VERSION 5.8 ;
BUSBITCHARS "[]" ;
DIVIDERCHAR "/" ;
UNITS
    DATABASE MICRONS 1000 ;
END UNITS

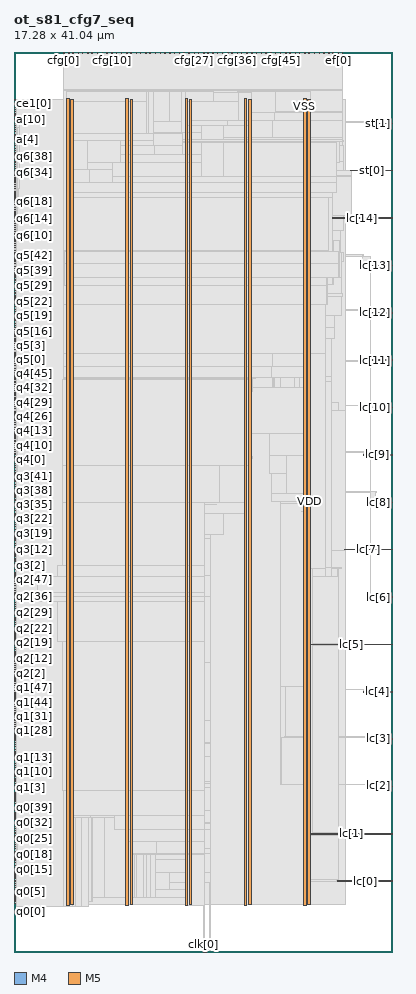
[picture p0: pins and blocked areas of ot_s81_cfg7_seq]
MACRO ot_s81_cfg7_seq
  FOREIGN ot_s81_cfg7_seq 0 0 ;
  CLASS BLOCK ;
  SIZE 17.28 BY 41.04 ;
  PIN a[0]
    DIRECTION OUTPUT ;
    USE SIGNAL ;
    PORT
      LAYER M4 ;
        RECT  0 36.96 0.084 36.984 ;
    END
  END a[0]
  PIN a[10]
    DIRECTION OUTPUT ;
    USE SIGNAL ;
    PORT
      LAYER M4 ;
        RECT  0 37.968 0.084 37.992 ;
    END
  END a[10]
  PIN a[11]
    DIRECTION OUTPUT ;
    USE SIGNAL ;
    PORT
      LAYER M4 ;
        RECT  0 38.112 0.084 38.136 ;
    END
  END a[11]
  PIN a[1]
    DIRECTION OUTPUT ;
    USE SIGNAL ;
    PORT
      LAYER M4 ;
        RECT  0 37.056 0.084 37.08 ;
    END
  END a[1]
  PIN a[2]
    DIRECTION OUTPUT ;
    USE SIGNAL ;
    PORT
      LAYER M4 ;
        RECT  0 37.152 0.084 37.176 ;
    END
  END a[2]
  PIN a[3]
    DIRECTION OUTPUT ;
    USE SIGNAL ;
    PORT
      LAYER M4 ;
        RECT  0 37.248 0.084 37.272 ;
    END
  END a[3]
  PIN a[4]
    DIRECTION OUTPUT ;
    USE SIGNAL ;
    PORT
      LAYER M4 ;
        RECT  0 37.392 0.084 37.416 ;
    END
  END a[4]
  PIN a[5]
    DIRECTION OUTPUT ;
    USE SIGNAL ;
    PORT
      LAYER M4 ;
        RECT  0 37.488 0.084 37.512 ;
    END
  END a[5]
  PIN a[6]
    DIRECTION OUTPUT ;
    USE SIGNAL ;
    PORT
      LAYER M4 ;
        RECT  0 37.584 0.084 37.608 ;
    END
  END a[6]
  PIN a[7]
    DIRECTION OUTPUT ;
    USE SIGNAL ;
    PORT
      LAYER M4 ;
        RECT  0 37.68 0.084 37.704 ;
    END
  END a[7]
  PIN a[8]
    DIRECTION OUTPUT ;
    USE SIGNAL ;
    PORT
      LAYER M4 ;
        RECT  0 37.776 0.084 37.8 ;
    END
  END a[8]
  PIN a[9]
    DIRECTION OUTPUT ;
    USE SIGNAL ;
    PORT
      LAYER M4 ;
        RECT  0 37.872 0.084 37.896 ;
    END
  END a[9]
  PIN ce0[0]
    DIRECTION OUTPUT ;
    USE SIGNAL ;
    PORT
      LAYER M4 ;
        RECT  0 38.208 0.084 38.232 ;
    END
  END ce0[0]
  PIN ce1[0]
    DIRECTION OUTPUT ;
    USE SIGNAL ;
    PORT
      LAYER M4 ;
        RECT  0 38.304 0.084 38.328 ;
    END
  END ce1[0]
  PIN ce2[0]
    DIRECTION OUTPUT ;
    USE SIGNAL ;
    PORT
      LAYER M4 ;
        RECT  0 38.4 0.084 38.424 ;
    END
  END ce2[0]
  PIN ce3[0]
    DIRECTION OUTPUT ;
    USE SIGNAL ;
    PORT
      LAYER M4 ;
        RECT  0 38.496 0.084 38.52 ;
    END
  END ce3[0]
  PIN ce4[0]
    DIRECTION OUTPUT ;
    USE SIGNAL ;
    PORT
      LAYER M4 ;
        RECT  0 38.592 0.084 38.616 ;
    END
  END ce4[0]
  PIN ce5[0]
    DIRECTION OUTPUT ;
    USE SIGNAL ;
    PORT
      LAYER M4 ;
        RECT  0 38.736 0.084 38.76 ;
    END
  END ce5[0]
  PIN ce6[0]
    DIRECTION OUTPUT ;
    USE SIGNAL ;
    PORT
      LAYER M4 ;
        RECT  0 38.832 0.084 38.856 ;
    END
  END ce6[0]
  PIN cfg[0]
    DIRECTION OUTPUT ;
    USE SIGNAL ;
    PORT
      LAYER M5 ;
        RECT  2.256 40.956 2.28 41.04 ;
    END
  END cfg[0]
  PIN cfg[10]
    DIRECTION OUTPUT ;
    USE SIGNAL ;
    PORT
      LAYER M5 ;
        RECT  4.464 40.956 4.488 41.04 ;
    END
  END cfg[10]
  PIN cfg[11]
    DIRECTION OUTPUT ;
    USE SIGNAL ;
    PORT
      LAYER M5 ;
        RECT  4.656 40.956 4.68 41.04 ;
    END
  END cfg[11]
  PIN cfg[12]
    DIRECTION OUTPUT ;
    USE SIGNAL ;
    PORT
      LAYER M5 ;
        RECT  4.896 40.956 4.92 41.04 ;
    END
  END cfg[12]
  PIN cfg[13]
    DIRECTION OUTPUT ;
    USE SIGNAL ;
    PORT
      LAYER M5 ;
        RECT  5.136 40.956 5.16 41.04 ;
    END
  END cfg[13]
  PIN cfg[14]
    DIRECTION OUTPUT ;
    USE SIGNAL ;
    PORT
      LAYER M5 ;
        RECT  5.328 40.956 5.352 41.04 ;
    END
  END cfg[14]
  PIN cfg[15]
    DIRECTION OUTPUT ;
    USE SIGNAL ;
    PORT
      LAYER M5 ;
        RECT  5.568 40.956 5.592 41.04 ;
    END
  END cfg[15]
  PIN cfg[16]
    DIRECTION OUTPUT ;
    USE SIGNAL ;
    PORT
      LAYER M5 ;
        RECT  5.76 40.956 5.784 41.04 ;
    END
  END cfg[16]
  PIN cfg[17]
    DIRECTION OUTPUT ;
    USE SIGNAL ;
    PORT
      LAYER M5 ;
        RECT  6 40.956 6.024 41.04 ;
    END
  END cfg[17]
  PIN cfg[18]
    DIRECTION OUTPUT ;
    USE SIGNAL ;
    PORT
      LAYER M5 ;
        RECT  6.192 40.956 6.216 41.04 ;
    END
  END cfg[18]
  PIN cfg[19]
    DIRECTION OUTPUT ;
    USE SIGNAL ;
    PORT
      LAYER M5 ;
        RECT  6.432 40.956 6.456 41.04 ;
    END
  END cfg[19]
  PIN cfg[1]
    DIRECTION OUTPUT ;
    USE SIGNAL ;
    PORT
      LAYER M5 ;
        RECT  2.496 40.956 2.52 41.04 ;
    END
  END cfg[1]
  PIN cfg[20]
    DIRECTION OUTPUT ;
    USE SIGNAL ;
    PORT
      LAYER M5 ;
        RECT  6.672 40.956 6.696 41.04 ;
    END
  END cfg[20]
  PIN cfg[21]
    DIRECTION OUTPUT ;
    USE SIGNAL ;
    PORT
      LAYER M5 ;
        RECT  6.864 40.956 6.888 41.04 ;
    END
  END cfg[21]
  PIN cfg[22]
    DIRECTION OUTPUT ;
    USE SIGNAL ;
    PORT
      LAYER M5 ;
        RECT  7.104 40.956 7.128 41.04 ;
    END
  END cfg[22]
  PIN cfg[23]
    DIRECTION OUTPUT ;
    USE SIGNAL ;
    PORT
      LAYER M5 ;
        RECT  7.296 40.956 7.32 41.04 ;
    END
  END cfg[23]
  PIN cfg[24]
    DIRECTION OUTPUT ;
    USE SIGNAL ;
    PORT
      LAYER M5 ;
        RECT  7.536 40.956 7.56 41.04 ;
    END
  END cfg[24]
  PIN cfg[25]
    DIRECTION OUTPUT ;
    USE SIGNAL ;
    PORT
      LAYER M5 ;
        RECT  7.728 40.956 7.752 41.04 ;
    END
  END cfg[25]
  PIN cfg[26]
    DIRECTION OUTPUT ;
    USE SIGNAL ;
    PORT
      LAYER M5 ;
        RECT  7.968 40.956 7.992 41.04 ;
    END
  END cfg[26]
  PIN cfg[27]
    DIRECTION OUTPUT ;
    USE SIGNAL ;
    PORT
      LAYER M5 ;
        RECT  8.208 40.956 8.232 41.04 ;
    END
  END cfg[27]
  PIN cfg[28]
    DIRECTION OUTPUT ;
    USE SIGNAL ;
    PORT
      LAYER M5 ;
        RECT  8.4 40.956 8.424 41.04 ;
    END
  END cfg[28]
  PIN cfg[29]
    DIRECTION OUTPUT ;
    USE SIGNAL ;
    PORT
      LAYER M5 ;
        RECT  8.64 40.956 8.664 41.04 ;
    END
  END cfg[29]
  PIN cfg[2]
    DIRECTION OUTPUT ;
    USE SIGNAL ;
    PORT
      LAYER M5 ;
        RECT  2.688 40.956 2.712 41.04 ;
    END
  END cfg[2]
  PIN cfg[30]
    DIRECTION OUTPUT ;
    USE SIGNAL ;
    PORT
      LAYER M5 ;
        RECT  8.832 40.956 8.856 41.04 ;
    END
  END cfg[30]
  PIN cfg[31]
    DIRECTION OUTPUT ;
    USE SIGNAL ;
    PORT
      LAYER M5 ;
        RECT  9.072 40.956 9.096 41.04 ;
    END
  END cfg[31]
  PIN cfg[32]
    DIRECTION OUTPUT ;
    USE SIGNAL ;
    PORT
      LAYER M5 ;
        RECT  9.264 40.956 9.288 41.04 ;
    END
  END cfg[32]
  PIN cfg[33]
    DIRECTION OUTPUT ;
    USE SIGNAL ;
    PORT
      LAYER M5 ;
        RECT  9.504 40.956 9.528 41.04 ;
    END
  END cfg[33]
  PIN cfg[34]
    DIRECTION OUTPUT ;
    USE SIGNAL ;
    PORT
      LAYER M5 ;
        RECT  9.744 40.956 9.768 41.04 ;
    END
  END cfg[34]
  PIN cfg[35]
    DIRECTION OUTPUT ;
    USE SIGNAL ;
    PORT
      LAYER M5 ;
        RECT  9.936 40.956 9.96 41.04 ;
    END
  END cfg[35]
  PIN cfg[36]
    DIRECTION OUTPUT ;
    USE SIGNAL ;
    PORT
      LAYER M5 ;
        RECT  10.176 40.956 10.2 41.04 ;
    END
  END cfg[36]
  PIN cfg[37]
    DIRECTION OUTPUT ;
    USE SIGNAL ;
    PORT
      LAYER M5 ;
        RECT  10.368 40.956 10.392 41.04 ;
    END
  END cfg[37]
  PIN cfg[38]
    DIRECTION OUTPUT ;
    USE SIGNAL ;
    PORT
      LAYER M5 ;
        RECT  10.608 40.956 10.632 41.04 ;
    END
  END cfg[38]
  PIN cfg[39]
    DIRECTION OUTPUT ;
    USE SIGNAL ;
    PORT
      LAYER M5 ;
        RECT  10.848 40.956 10.872 41.04 ;
    END
  END cfg[39]
  PIN cfg[3]
    DIRECTION OUTPUT ;
    USE SIGNAL ;
    PORT
      LAYER M5 ;
        RECT  2.928 40.956 2.952 41.04 ;
    END
  END cfg[3]
  PIN cfg[40]
    DIRECTION OUTPUT ;
    USE SIGNAL ;
    PORT
      LAYER M5 ;
        RECT  11.04 40.956 11.064 41.04 ;
    END
  END cfg[40]
  PIN cfg[41]
    DIRECTION OUTPUT ;
    USE SIGNAL ;
    PORT
      LAYER M5 ;
        RECT  11.28 40.956 11.304 41.04 ;
    END
  END cfg[41]
  PIN cfg[42]
    DIRECTION OUTPUT ;
    USE SIGNAL ;
    PORT
      LAYER M5 ;
        RECT  11.472 40.956 11.496 41.04 ;
    END
  END cfg[42]
  PIN cfg[43]
    DIRECTION OUTPUT ;
    USE SIGNAL ;
    PORT
      LAYER M5 ;
        RECT  11.712 40.956 11.736 41.04 ;
    END
  END cfg[43]
  PIN cfg[44]
    DIRECTION OUTPUT ;
    USE SIGNAL ;
    PORT
      LAYER M5 ;
        RECT  11.904 40.956 11.928 41.04 ;
    END
  END cfg[44]
  PIN cfg[45]
    DIRECTION OUTPUT ;
    USE SIGNAL ;
    PORT
      LAYER M5 ;
        RECT  12.144 40.956 12.168 41.04 ;
    END
  END cfg[45]
  PIN cfg[46]
    DIRECTION OUTPUT ;
    USE SIGNAL ;
    PORT
      LAYER M5 ;
        RECT  12.384 40.956 12.408 41.04 ;
    END
  END cfg[46]
  PIN cfg[47]
    DIRECTION OUTPUT ;
    USE SIGNAL ;
    PORT
      LAYER M5 ;
        RECT  12.576 40.956 12.6 41.04 ;
    END
  END cfg[47]
  PIN cfg[48]
    DIRECTION OUTPUT ;
    USE SIGNAL ;
    PORT
      LAYER M5 ;
        RECT  12.816 40.956 12.84 41.04 ;
    END
  END cfg[48]
  PIN cfg[49]
    DIRECTION OUTPUT ;
    USE SIGNAL ;
    PORT
      LAYER M5 ;
        RECT  13.008 40.956 13.032 41.04 ;
    END
  END cfg[49]
  PIN cfg[4]
    DIRECTION OUTPUT ;
    USE SIGNAL ;
    PORT
      LAYER M5 ;
        RECT  3.12 40.956 3.144 41.04 ;
    END
  END cfg[4]
  PIN cfg[50]
    DIRECTION OUTPUT ;
    USE SIGNAL ;
    PORT
      LAYER M5 ;
        RECT  13.248 40.956 13.272 41.04 ;
    END
  END cfg[50]
  PIN cfg[51]
    DIRECTION OUTPUT ;
    USE SIGNAL ;
    PORT
      LAYER M5 ;
        RECT  13.44 40.956 13.464 41.04 ;
    END
  END cfg[51]
  PIN cfg[52]
    DIRECTION OUTPUT ;
    USE SIGNAL ;
    PORT
      LAYER M5 ;
        RECT  13.68 40.956 13.704 41.04 ;
    END
  END cfg[52]
  PIN cfg[53]
    DIRECTION OUTPUT ;
    USE SIGNAL ;
    PORT
      LAYER M5 ;
        RECT  13.92 40.956 13.944 41.04 ;
    END
  END cfg[53]
  PIN cfg[5]
    DIRECTION OUTPUT ;
    USE SIGNAL ;
    PORT
      LAYER M5 ;
        RECT  3.36 40.956 3.384 41.04 ;
    END
  END cfg[5]
  PIN cfg[6]
    DIRECTION OUTPUT ;
    USE SIGNAL ;
    PORT
      LAYER M5 ;
        RECT  3.552 40.956 3.576 41.04 ;
    END
  END cfg[6]
  PIN cfg[7]
    DIRECTION OUTPUT ;
    USE SIGNAL ;
    PORT
      LAYER M5 ;
        RECT  3.792 40.956 3.816 41.04 ;
    END
  END cfg[7]
  PIN cfg[8]
    DIRECTION OUTPUT ;
    USE SIGNAL ;
    PORT
      LAYER M5 ;
        RECT  4.032 40.956 4.056 41.04 ;
    END
  END cfg[8]
  PIN cfg[9]
    DIRECTION OUTPUT ;
    USE SIGNAL ;
    PORT
      LAYER M5 ;
        RECT  4.224 40.956 4.248 41.04 ;
    END
  END cfg[9]
  PIN clk[0]
    DIRECTION INPUT ;
    USE SIGNAL ;
    PORT
      LAYER M5 ;
        RECT  8.64 0 8.664 0.084 ;
    END
  END clk[0]
  PIN ef[0]
    DIRECTION INPUT ;
    USE SIGNAL ;
    PORT
      LAYER M5 ;
        RECT  14.784 40.956 14.808 41.04 ;
    END
  END ef[0]
  PIN ef[1]
    DIRECTION INPUT ;
    USE SIGNAL ;
    PORT
      LAYER M5 ;
        RECT  14.976 40.956 15 41.04 ;
    END
  END ef[1]
  PIN go_e[0]
    DIRECTION OUTPUT ;
    USE SIGNAL ;
    PORT
      LAYER M5 ;
        RECT  14.112 40.956 14.136 41.04 ;
    END
  END go_e[0]
  PIN go_tag[0]
    DIRECTION OUTPUT ;
    USE SIGNAL ;
    PORT
      LAYER M5 ;
        RECT  14.352 40.956 14.376 41.04 ;
    END
  END go_tag[0]
  PIN go_tag[1]
    DIRECTION OUTPUT ;
    USE SIGNAL ;
    PORT
      LAYER M5 ;
        RECT  14.544 40.956 14.568 41.04 ;
    END
  END go_tag[1]
  PIN lc[0]
    DIRECTION INPUT ;
    USE SIGNAL ;
    PORT
      LAYER M4 ;
        RECT  17.196 3.216 17.28 3.24 ;
    END
    PORT
      LAYER M4 ;
        RECT  14.773 3.216 17.244 3.24 ;
    END
  END lc[0]
  PIN lc[10]
    DIRECTION INPUT ;
    USE SIGNAL ;
    PORT
      LAYER M4 ;
        RECT  17.196 24.816 17.28 24.84 ;
    END
    PORT
      LAYER M4 ;
        RECT  16.477 24.816 17.244 24.84 ;
    END
  END lc[10]
  PIN lc[11]
    DIRECTION INPUT ;
    USE SIGNAL ;
    PORT
      LAYER M4 ;
        RECT  17.196 26.976 17.28 27 ;
    END
    PORT
      LAYER M4 ;
        RECT  15.973 26.976 17.244 27 ;
    END
  END lc[11]
  PIN lc[12]
    DIRECTION INPUT ;
    USE SIGNAL ;
    PORT
      LAYER M4 ;
        RECT  17.196 29.136 17.28 29.16 ;
    END
    PORT
      LAYER M4 ;
        RECT  15.937 29.136 17.244 29.16 ;
    END
  END lc[12]
  PIN lc[13]
    DIRECTION INPUT ;
    USE SIGNAL ;
    PORT
      LAYER M4 ;
        RECT  17.196 31.296 17.28 31.32 ;
    END
    PORT
      LAYER M4 ;
        RECT  15.901 31.296 17.244 31.32 ;
    END
  END lc[13]
  PIN lc[14]
    DIRECTION INPUT ;
    USE SIGNAL ;
    PORT
      LAYER M4 ;
        RECT  17.196 33.456 17.28 33.48 ;
    END
    PORT
      LAYER M4 ;
        RECT  14.537 33.456 17.244 33.48 ;
    END
  END lc[14]
  PIN lc[1]
    DIRECTION INPUT ;
    USE SIGNAL ;
    PORT
      LAYER M4 ;
        RECT  17.196 5.376 17.28 5.4 ;
    END
    PORT
      LAYER M4 ;
        RECT  13.504 5.376 17.244 5.4 ;
    END
  END lc[1]
  PIN lc[2]
    DIRECTION INPUT ;
    USE SIGNAL ;
    PORT
      LAYER M4 ;
        RECT  17.196 7.536 17.28 7.56 ;
    END
    PORT
      LAYER M4 ;
        RECT  17.161 7.536 17.201 7.656 ;
    END
    PORT
      LAYER M4 ;
        RECT  17.201 7.536 17.244 7.56 ;
    END
  END lc[2]
  PIN lc[3]
    DIRECTION INPUT ;
    USE SIGNAL ;
    PORT
      LAYER M4 ;
        RECT  17.196 9.696 17.28 9.72 ;
    END
    PORT
      LAYER M4 ;
        RECT  17.161 9.696 17.201 9.816 ;
    END
    PORT
      LAYER M4 ;
        RECT  17.201 9.696 17.244 9.72 ;
    END
  END lc[3]
  PIN lc[4]
    DIRECTION INPUT ;
    USE SIGNAL ;
    PORT
      LAYER M4 ;
        RECT  17.196 11.856 17.28 11.88 ;
    END
    PORT
      LAYER M4 ;
        RECT  15.937 11.856 17.244 11.88 ;
    END
  END lc[4]
  PIN lc[5]
    DIRECTION INPUT ;
    USE SIGNAL ;
    PORT
      LAYER M4 ;
        RECT  17.196 14.016 17.28 14.04 ;
    END
    PORT
      LAYER M4 ;
        RECT  13.504 14.016 17.244 14.04 ;
    END
  END lc[5]
  PIN lc[6]
    DIRECTION INPUT ;
    USE SIGNAL ;
    PORT
      LAYER M4 ;
        RECT  17.196 16.176 17.28 16.2 ;
    END
    PORT
      LAYER M4 ;
        RECT  16.225 16.176 17.244 16.2 ;
    END
  END lc[6]
  PIN lc[7]
    DIRECTION INPUT ;
    USE SIGNAL ;
    PORT
      LAYER M4 ;
        RECT  17.196 18.336 17.28 18.36 ;
    END
    PORT
      LAYER M4 ;
        RECT  15.073 18.336 17.244 18.36 ;
    END
  END lc[7]
  PIN lc[8]
    DIRECTION INPUT ;
    USE SIGNAL ;
    PORT
      LAYER M4 ;
        RECT  17.196 20.496 17.28 20.52 ;
    END
    PORT
      LAYER M4 ;
        RECT  16.477 20.496 17.244 20.52 ;
    END
  END lc[8]
  PIN lc[9]
    DIRECTION INPUT ;
    USE SIGNAL ;
    PORT
      LAYER M4 ;
        RECT  17.196 22.656 17.28 22.68 ;
    END
    PORT
      LAYER M4 ;
        RECT  15.937 22.656 17.244 22.68 ;
    END
  END lc[9]
  PIN q0[0]
    DIRECTION INPUT ;
    USE SIGNAL ;
    PORT
      LAYER M4 ;
        RECT  0 2.208 0.084 2.232 ;
    END
  END q0[0]
  PIN q0[10]
    DIRECTION INPUT ;
    USE SIGNAL ;
    PORT
      LAYER M4 ;
        RECT  0 3.216 0.084 3.24 ;
    END
  END q0[10]
  PIN q0[11]
    DIRECTION INPUT ;
    USE SIGNAL ;
    PORT
      LAYER M4 ;
        RECT  0 3.36 0.084 3.384 ;
    END
  END q0[11]
  PIN q0[12]
    DIRECTION INPUT ;
    USE SIGNAL ;
    PORT
      LAYER M4 ;
        RECT  0 3.456 0.084 3.48 ;
    END
  END q0[12]
  PIN q0[13]
    DIRECTION INPUT ;
    USE SIGNAL ;
    PORT
      LAYER M4 ;
        RECT  0 3.552 0.084 3.576 ;
    END
  END q0[13]
  PIN q0[14]
    DIRECTION INPUT ;
    USE SIGNAL ;
    PORT
      LAYER M4 ;
        RECT  0 3.648 0.084 3.672 ;
    END
  END q0[14]
  PIN q0[15]
    DIRECTION INPUT ;
    USE SIGNAL ;
    PORT
      LAYER M4 ;
        RECT  0 3.744 0.084 3.768 ;
    END
  END q0[15]
  PIN q0[16]
    DIRECTION INPUT ;
    USE SIGNAL ;
    PORT
      LAYER M4 ;
        RECT  0 3.84 0.084 3.864 ;
    END
  END q0[16]
  PIN q0[17]
    DIRECTION INPUT ;
    USE SIGNAL ;
    PORT
      LAYER M4 ;
        RECT  0 3.936 0.084 3.96 ;
    END
  END q0[17]
  PIN q0[18]
    DIRECTION INPUT ;
    USE SIGNAL ;
    PORT
      LAYER M4 ;
        RECT  0 4.08 0.084 4.104 ;
    END
  END q0[18]
  PIN q0[19]
    DIRECTION INPUT ;
    USE SIGNAL ;
    PORT
      LAYER M4 ;
        RECT  0 4.176 0.084 4.2 ;
    END
  END q0[19]
  PIN q0[1]
    DIRECTION INPUT ;
    USE SIGNAL ;
    PORT
      LAYER M4 ;
        RECT  0 2.304 0.084 2.328 ;
    END
  END q0[1]
  PIN q0[20]
    DIRECTION INPUT ;
    USE SIGNAL ;
    PORT
      LAYER M4 ;
        RECT  0 4.272 0.084 4.296 ;
    END
  END q0[20]
  PIN q0[21]
    DIRECTION INPUT ;
    USE SIGNAL ;
    PORT
      LAYER M4 ;
        RECT  0 4.368 0.084 4.392 ;
    END
  END q0[21]
  PIN q0[22]
    DIRECTION INPUT ;
    USE SIGNAL ;
    PORT
      LAYER M4 ;
        RECT  0 4.464 0.084 4.488 ;
    END
  END q0[22]
  PIN q0[23]
    DIRECTION INPUT ;
    USE SIGNAL ;
    PORT
      LAYER M4 ;
        RECT  0 4.56 0.084 4.584 ;
    END
  END q0[23]
  PIN q0[24]
    DIRECTION INPUT ;
    USE SIGNAL ;
    PORT
      LAYER M4 ;
        RECT  0 4.704 0.084 4.728 ;
    END
  END q0[24]
  PIN q0[25]
    DIRECTION INPUT ;
    USE SIGNAL ;
    PORT
      LAYER M4 ;
        RECT  0 4.8 0.084 4.824 ;
    END
  END q0[25]
  PIN q0[26]
    DIRECTION INPUT ;
    USE SIGNAL ;
    PORT
      LAYER M4 ;
        RECT  0 4.896 0.084 4.92 ;
    END
  END q0[26]
  PIN q0[27]
    DIRECTION INPUT ;
    USE SIGNAL ;
    PORT
      LAYER M4 ;
        RECT  0 4.992 0.084 5.016 ;
    END
  END q0[27]
  PIN q0[28]
    DIRECTION INPUT ;
    USE SIGNAL ;
    PORT
      LAYER M4 ;
        RECT  0 5.088 0.084 5.112 ;
    END
  END q0[28]
  PIN q0[29]
    DIRECTION INPUT ;
    USE SIGNAL ;
    PORT
      LAYER M4 ;
        RECT  0 5.184 0.084 5.208 ;
    END
  END q0[29]
  PIN q0[2]
    DIRECTION INPUT ;
    USE SIGNAL ;
    PORT
      LAYER M4 ;
        RECT  0 2.4 0.084 2.424 ;
    END
  END q0[2]
  PIN q0[30]
    DIRECTION INPUT ;
    USE SIGNAL ;
    PORT
      LAYER M4 ;
        RECT  0 5.28 0.084 5.304 ;
    END
  END q0[30]
  PIN q0[31]
    DIRECTION INPUT ;
    USE SIGNAL ;
    PORT
      LAYER M4 ;
        RECT  0 5.424 0.084 5.448 ;
    END
  END q0[31]
  PIN q0[32]
    DIRECTION INPUT ;
    USE SIGNAL ;
    PORT
      LAYER M4 ;
        RECT  0 5.52 0.084 5.544 ;
    END
  END q0[32]
  PIN q0[33]
    DIRECTION INPUT ;
    USE SIGNAL ;
    PORT
      LAYER M4 ;
        RECT  0 5.616 0.084 5.64 ;
    END
  END q0[33]
  PIN q0[34]
    DIRECTION INPUT ;
    USE SIGNAL ;
    PORT
      LAYER M4 ;
        RECT  0 5.712 0.084 5.736 ;
    END
  END q0[34]
  PIN q0[35]
    DIRECTION INPUT ;
    USE SIGNAL ;
    PORT
      LAYER M4 ;
        RECT  0 5.808 0.084 5.832 ;
    END
  END q0[35]
  PIN q0[36]
    DIRECTION INPUT ;
    USE SIGNAL ;
    PORT
      LAYER M4 ;
        RECT  0 5.904 0.084 5.928 ;
    END
  END q0[36]
  PIN q0[37]
    DIRECTION INPUT ;
    USE SIGNAL ;
    PORT
      LAYER M4 ;
        RECT  0 6.048 0.084 6.072 ;
    END
  END q0[37]
  PIN q0[38]
    DIRECTION INPUT ;
    USE SIGNAL ;
    PORT
      LAYER M4 ;
        RECT  0 6.144 0.084 6.168 ;
    END
  END q0[38]
  PIN q0[39]
    DIRECTION INPUT ;
    USE SIGNAL ;
    PORT
      LAYER M4 ;
        RECT  0 6.24 0.084 6.264 ;
    END
  END q0[39]
  PIN q0[3]
    DIRECTION INPUT ;
    USE SIGNAL ;
    PORT
      LAYER M4 ;
        RECT  0 2.496 0.084 2.52 ;
    END
  END q0[3]
  PIN q0[40]
    DIRECTION INPUT ;
    USE SIGNAL ;
    PORT
      LAYER M4 ;
        RECT  0 6.336 0.084 6.36 ;
    END
  END q0[40]
  PIN q0[41]
    DIRECTION INPUT ;
    USE SIGNAL ;
    PORT
      LAYER M4 ;
        RECT  0 6.432 0.084 6.456 ;
    END
  END q0[41]
  PIN q0[42]
    DIRECTION INPUT ;
    USE SIGNAL ;
    PORT
      LAYER M4 ;
        RECT  0 6.528 0.084 6.552 ;
    END
  END q0[42]
  PIN q0[43]
    DIRECTION INPUT ;
    USE SIGNAL ;
    PORT
      LAYER M4 ;
        RECT  0 6.624 0.084 6.648 ;
    END
  END q0[43]
  PIN q0[44]
    DIRECTION INPUT ;
    USE SIGNAL ;
    PORT
      LAYER M4 ;
        RECT  0 6.768 0.084 6.792 ;
    END
  END q0[44]
  PIN q0[45]
    DIRECTION INPUT ;
    USE SIGNAL ;
    PORT
      LAYER M4 ;
        RECT  0 6.864 0.084 6.888 ;
    END
  END q0[45]
  PIN q0[46]
    DIRECTION INPUT ;
    USE SIGNAL ;
    PORT
      LAYER M4 ;
        RECT  0 6.96 0.084 6.984 ;
    END
  END q0[46]
  PIN q0[47]
    DIRECTION INPUT ;
    USE SIGNAL ;
    PORT
      LAYER M4 ;
        RECT  0 7.056 0.084 7.08 ;
    END
  END q0[47]
  PIN q0[4]
    DIRECTION INPUT ;
    USE SIGNAL ;
    PORT
      LAYER M4 ;
        RECT  0 2.592 0.084 2.616 ;
    END
  END q0[4]
  PIN q0[5]
    DIRECTION INPUT ;
    USE SIGNAL ;
    PORT
      LAYER M4 ;
        RECT  0 2.736 0.084 2.76 ;
    END
  END q0[5]
  PIN q0[6]
    DIRECTION INPUT ;
    USE SIGNAL ;
    PORT
      LAYER M4 ;
        RECT  0 2.832 0.084 2.856 ;
    END
  END q0[6]
  PIN q0[7]
    DIRECTION INPUT ;
    USE SIGNAL ;
    PORT
      LAYER M4 ;
        RECT  0 2.928 0.084 2.952 ;
    END
  END q0[7]
  PIN q0[8]
    DIRECTION INPUT ;
    USE SIGNAL ;
    PORT
      LAYER M4 ;
        RECT  0 3.024 0.084 3.048 ;
    END
  END q0[8]
  PIN q0[9]
    DIRECTION INPUT ;
    USE SIGNAL ;
    PORT
      LAYER M4 ;
        RECT  0 3.12 0.084 3.144 ;
    END
  END q0[9]
  PIN q1[0]
    DIRECTION INPUT ;
    USE SIGNAL ;
    PORT
      LAYER M4 ;
        RECT  0 7.152 0.084 7.176 ;
    END
  END q1[0]
  PIN q1[10]
    DIRECTION INPUT ;
    USE SIGNAL ;
    PORT
      LAYER M4 ;
        RECT  0 8.208 0.084 8.232 ;
    END
  END q1[10]
  PIN q1[11]
    DIRECTION INPUT ;
    USE SIGNAL ;
    PORT
      LAYER M4 ;
        RECT  0 8.304 0.084 8.328 ;
    END
  END q1[11]
  PIN q1[12]
    DIRECTION INPUT ;
    USE SIGNAL ;
    PORT
      LAYER M4 ;
        RECT  0 8.4 0.084 8.424 ;
    END
  END q1[12]
  PIN q1[13]
    DIRECTION INPUT ;
    USE SIGNAL ;
    PORT
      LAYER M4 ;
        RECT  0 8.496 0.084 8.52 ;
    END
  END q1[13]
  PIN q1[14]
    DIRECTION INPUT ;
    USE SIGNAL ;
    PORT
      LAYER M4 ;
        RECT  0 8.592 0.084 8.616 ;
    END
  END q1[14]
  PIN q1[15]
    DIRECTION INPUT ;
    USE SIGNAL ;
    PORT
      LAYER M4 ;
        RECT  0 8.736 0.084 8.76 ;
    END
  END q1[15]
  PIN q1[16]
    DIRECTION INPUT ;
    USE SIGNAL ;
    PORT
      LAYER M4 ;
        RECT  0 8.832 0.084 8.856 ;
    END
  END q1[16]
  PIN q1[17]
    DIRECTION INPUT ;
    USE SIGNAL ;
    PORT
      LAYER M4 ;
        RECT  0 8.928 0.084 8.952 ;
    END
  END q1[17]
  PIN q1[18]
    DIRECTION INPUT ;
    USE SIGNAL ;
    PORT
      LAYER M4 ;
        RECT  0 9.024 0.084 9.048 ;
    END
  END q1[18]
  PIN q1[19]
    DIRECTION INPUT ;
    USE SIGNAL ;
    PORT
      LAYER M4 ;
        RECT  0 9.12 0.084 9.144 ;
    END
  END q1[19]
  PIN q1[1]
    DIRECTION INPUT ;
    USE SIGNAL ;
    PORT
      LAYER M4 ;
        RECT  0 7.248 0.084 7.272 ;
    END
  END q1[1]
  PIN q1[20]
    DIRECTION INPUT ;
    USE SIGNAL ;
    PORT
      LAYER M4 ;
        RECT  0 9.216 0.084 9.24 ;
    END
  END q1[20]
  PIN q1[21]
    DIRECTION INPUT ;
    USE SIGNAL ;
    PORT
      LAYER M4 ;
        RECT  0 9.36 0.084 9.384 ;
    END
  END q1[21]
  PIN q1[22]
    DIRECTION INPUT ;
    USE SIGNAL ;
    PORT
      LAYER M4 ;
        RECT  0 9.456 0.084 9.48 ;
    END
  END q1[22]
  PIN q1[23]
    DIRECTION INPUT ;
    USE SIGNAL ;
    PORT
      LAYER M4 ;
        RECT  0 9.552 0.084 9.576 ;
    END
  END q1[23]
  PIN q1[24]
    DIRECTION INPUT ;
    USE SIGNAL ;
    PORT
      LAYER M4 ;
        RECT  0 9.648 0.084 9.672 ;
    END
  END q1[24]
  PIN q1[25]
    DIRECTION INPUT ;
    USE SIGNAL ;
    PORT
      LAYER M4 ;
        RECT  0 9.744 0.084 9.768 ;
    END
  END q1[25]
  PIN q1[26]
    DIRECTION INPUT ;
    USE SIGNAL ;
    PORT
      LAYER M4 ;
        RECT  0 9.84 0.084 9.864 ;
    END
  END q1[26]
  PIN q1[27]
    DIRECTION INPUT ;
    USE SIGNAL ;
    PORT
      LAYER M4 ;
        RECT  0 9.936 0.084 9.96 ;
    END
  END q1[27]
  PIN q1[28]
    DIRECTION INPUT ;
    USE SIGNAL ;
    PORT
      LAYER M4 ;
        RECT  0 10.08 0.084 10.104 ;
    END
  END q1[28]
  PIN q1[29]
    DIRECTION INPUT ;
    USE SIGNAL ;
    PORT
      LAYER M4 ;
        RECT  0 10.176 0.084 10.2 ;
    END
  END q1[29]
  PIN q1[2]
    DIRECTION INPUT ;
    USE SIGNAL ;
    PORT
      LAYER M4 ;
        RECT  0 7.392 0.084 7.416 ;
    END
  END q1[2]
  PIN q1[30]
    DIRECTION INPUT ;
    USE SIGNAL ;
    PORT
      LAYER M4 ;
        RECT  0 10.272 0.084 10.296 ;
    END
  END q1[30]
  PIN q1[31]
    DIRECTION INPUT ;
    USE SIGNAL ;
    PORT
      LAYER M4 ;
        RECT  0 10.368 0.084 10.392 ;
    END
  END q1[31]
  PIN q1[32]
    DIRECTION INPUT ;
    USE SIGNAL ;
    PORT
      LAYER M4 ;
        RECT  0 10.464 0.084 10.488 ;
    END
  END q1[32]
  PIN q1[33]
    DIRECTION INPUT ;
    USE SIGNAL ;
    PORT
      LAYER M4 ;
        RECT  0 10.56 0.084 10.584 ;
    END
  END q1[33]
  PIN q1[34]
    DIRECTION INPUT ;
    USE SIGNAL ;
    PORT
      LAYER M4 ;
        RECT  0 10.704 0.084 10.728 ;
    END
  END q1[34]
  PIN q1[35]
    DIRECTION INPUT ;
    USE SIGNAL ;
    PORT
      LAYER M4 ;
        RECT  0 10.8 0.084 10.824 ;
    END
  END q1[35]
  PIN q1[36]
    DIRECTION INPUT ;
    USE SIGNAL ;
    PORT
      LAYER M4 ;
        RECT  0 10.896 0.084 10.92 ;
    END
  END q1[36]
  PIN q1[37]
    DIRECTION INPUT ;
    USE SIGNAL ;
    PORT
      LAYER M4 ;
        RECT  0 10.992 0.084 11.016 ;
    END
  END q1[37]
  PIN q1[38]
    DIRECTION INPUT ;
    USE SIGNAL ;
    PORT
      LAYER M4 ;
        RECT  0 11.088 0.084 11.112 ;
    END
  END q1[38]
  PIN q1[39]
    DIRECTION INPUT ;
    USE SIGNAL ;
    PORT
      LAYER M4 ;
        RECT  0 11.184 0.084 11.208 ;
    END
  END q1[39]
  PIN q1[3]
    DIRECTION INPUT ;
    USE SIGNAL ;
    PORT
      LAYER M4 ;
        RECT  0 7.488 0.084 7.512 ;
    END
  END q1[3]
  PIN q1[40]
    DIRECTION INPUT ;
    USE SIGNAL ;
    PORT
      LAYER M4 ;
        RECT  0 11.28 0.084 11.304 ;
    END
  END q1[40]
  PIN q1[41]
    DIRECTION INPUT ;
    USE SIGNAL ;
    PORT
      LAYER M4 ;
        RECT  0 11.424 0.084 11.448 ;
    END
  END q1[41]
  PIN q1[42]
    DIRECTION INPUT ;
    USE SIGNAL ;
    PORT
      LAYER M4 ;
        RECT  0 11.52 0.084 11.544 ;
    END
  END q1[42]
  PIN q1[43]
    DIRECTION INPUT ;
    USE SIGNAL ;
    PORT
      LAYER M4 ;
        RECT  0 11.616 0.084 11.64 ;
    END
  END q1[43]
  PIN q1[44]
    DIRECTION INPUT ;
    USE SIGNAL ;
    PORT
      LAYER M4 ;
        RECT  0 11.712 0.084 11.736 ;
    END
  END q1[44]
  PIN q1[45]
    DIRECTION INPUT ;
    USE SIGNAL ;
    PORT
      LAYER M4 ;
        RECT  0 11.808 0.084 11.832 ;
    END
  END q1[45]
  PIN q1[46]
    DIRECTION INPUT ;
    USE SIGNAL ;
    PORT
      LAYER M4 ;
        RECT  0 11.904 0.084 11.928 ;
    END
  END q1[46]
  PIN q1[47]
    DIRECTION INPUT ;
    USE SIGNAL ;
    PORT
      LAYER M4 ;
        RECT  0 12.048 0.084 12.072 ;
    END
  END q1[47]
  PIN q1[4]
    DIRECTION INPUT ;
    USE SIGNAL ;
    PORT
      LAYER M4 ;
        RECT  0 7.584 0.084 7.608 ;
    END
  END q1[4]
  PIN q1[5]
    DIRECTION INPUT ;
    USE SIGNAL ;
    PORT
      LAYER M4 ;
        RECT  0 7.68 0.084 7.704 ;
    END
  END q1[5]
  PIN q1[6]
    DIRECTION INPUT ;
    USE SIGNAL ;
    PORT
      LAYER M4 ;
        RECT  0 7.776 0.084 7.8 ;
    END
  END q1[6]
  PIN q1[7]
    DIRECTION INPUT ;
    USE SIGNAL ;
    PORT
      LAYER M4 ;
        RECT  0 7.872 0.084 7.896 ;
    END
  END q1[7]
  PIN q1[8]
    DIRECTION INPUT ;
    USE SIGNAL ;
    PORT
      LAYER M4 ;
        RECT  0 8.016 0.084 8.04 ;
    END
  END q1[8]
  PIN q1[9]
    DIRECTION INPUT ;
    USE SIGNAL ;
    PORT
      LAYER M4 ;
        RECT  0 8.112 0.084 8.136 ;
    END
  END q1[9]
  PIN q2[0]
    DIRECTION INPUT ;
    USE SIGNAL ;
    PORT
      LAYER M4 ;
        RECT  0 12.144 0.084 12.168 ;
    END
  END q2[0]
  PIN q2[10]
    DIRECTION INPUT ;
    USE SIGNAL ;
    PORT
      LAYER M4 ;
        RECT  0 13.152 0.084 13.176 ;
    END
  END q2[10]
  PIN q2[11]
    DIRECTION INPUT ;
    USE SIGNAL ;
    PORT
      LAYER M4 ;
        RECT  0 13.248 0.084 13.272 ;
    END
  END q2[11]
  PIN q2[12]
    DIRECTION INPUT ;
    USE SIGNAL ;
    PORT
      LAYER M4 ;
        RECT  0 13.392 0.084 13.416 ;
    END
  END q2[12]
  PIN q2[13]
    DIRECTION INPUT ;
    USE SIGNAL ;
    PORT
      LAYER M4 ;
        RECT  0 13.488 0.084 13.512 ;
    END
  END q2[13]
  PIN q2[14]
    DIRECTION INPUT ;
    USE SIGNAL ;
    PORT
      LAYER M4 ;
        RECT  0 13.584 0.084 13.608 ;
    END
  END q2[14]
  PIN q2[15]
    DIRECTION INPUT ;
    USE SIGNAL ;
    PORT
      LAYER M4 ;
        RECT  0 13.68 0.084 13.704 ;
    END
  END q2[15]
  PIN q2[16]
    DIRECTION INPUT ;
    USE SIGNAL ;
    PORT
      LAYER M4 ;
        RECT  0 13.776 0.084 13.8 ;
    END
  END q2[16]
  PIN q2[17]
    DIRECTION INPUT ;
    USE SIGNAL ;
    PORT
      LAYER M4 ;
        RECT  0 13.872 0.084 13.896 ;
    END
  END q2[17]
  PIN q2[18]
    DIRECTION INPUT ;
    USE SIGNAL ;
    PORT
      LAYER M4 ;
        RECT  0 13.968 0.084 13.992 ;
    END
  END q2[18]
  PIN q2[19]
    DIRECTION INPUT ;
    USE SIGNAL ;
    PORT
      LAYER M4 ;
        RECT  0 14.112 0.084 14.136 ;
    END
  END q2[19]
  PIN q2[1]
    DIRECTION INPUT ;
    USE SIGNAL ;
    PORT
      LAYER M4 ;
        RECT  0 12.24 0.084 12.264 ;
    END
  END q2[1]
  PIN q2[20]
    DIRECTION INPUT ;
    USE SIGNAL ;
    PORT
      LAYER M4 ;
        RECT  0 14.208 0.084 14.232 ;
    END
  END q2[20]
  PIN q2[21]
    DIRECTION INPUT ;
    USE SIGNAL ;
    PORT
      LAYER M4 ;
        RECT  0 14.304 0.084 14.328 ;
    END
  END q2[21]
  PIN q2[22]
    DIRECTION INPUT ;
    USE SIGNAL ;
    PORT
      LAYER M4 ;
        RECT  0 14.4 0.084 14.424 ;
    END
  END q2[22]
  PIN q2[23]
    DIRECTION INPUT ;
    USE SIGNAL ;
    PORT
      LAYER M4 ;
        RECT  0 14.496 0.084 14.52 ;
    END
  END q2[23]
  PIN q2[24]
    DIRECTION INPUT ;
    USE SIGNAL ;
    PORT
      LAYER M4 ;
        RECT  0 14.592 0.084 14.616 ;
    END
  END q2[24]
  PIN q2[25]
    DIRECTION INPUT ;
    USE SIGNAL ;
    PORT
      LAYER M4 ;
        RECT  0 14.736 0.084 14.76 ;
    END
  END q2[25]
  PIN q2[26]
    DIRECTION INPUT ;
    USE SIGNAL ;
    PORT
      LAYER M4 ;
        RECT  0 14.832 0.084 14.856 ;
    END
  END q2[26]
  PIN q2[27]
    DIRECTION INPUT ;
    USE SIGNAL ;
    PORT
      LAYER M4 ;
        RECT  0 14.928 0.084 14.952 ;
    END
  END q2[27]
  PIN q2[28]
    DIRECTION INPUT ;
    USE SIGNAL ;
    PORT
      LAYER M4 ;
        RECT  0 15.024 0.084 15.048 ;
    END
  END q2[28]
  PIN q2[29]
    DIRECTION INPUT ;
    USE SIGNAL ;
    PORT
      LAYER M4 ;
        RECT  0 15.12 0.084 15.144 ;
    END
  END q2[29]
  PIN q2[2]
    DIRECTION INPUT ;
    USE SIGNAL ;
    PORT
      LAYER M4 ;
        RECT  0 12.336 0.084 12.36 ;
    END
  END q2[2]
  PIN q2[30]
    DIRECTION INPUT ;
    USE SIGNAL ;
    PORT
      LAYER M4 ;
        RECT  0 15.216 0.084 15.24 ;
    END
  END q2[30]
  PIN q2[31]
    DIRECTION INPUT ;
    USE SIGNAL ;
    PORT
      LAYER M4 ;
        RECT  0 15.36 0.084 15.384 ;
    END
  END q2[31]
  PIN q2[32]
    DIRECTION INPUT ;
    USE SIGNAL ;
    PORT
      LAYER M4 ;
        RECT  0 15.456 0.084 15.48 ;
    END
  END q2[32]
  PIN q2[33]
    DIRECTION INPUT ;
    USE SIGNAL ;
    PORT
      LAYER M4 ;
        RECT  0 15.552 0.084 15.576 ;
    END
  END q2[33]
  PIN q2[34]
    DIRECTION INPUT ;
    USE SIGNAL ;
    PORT
      LAYER M4 ;
        RECT  0 15.648 0.084 15.672 ;
    END
  END q2[34]
  PIN q2[35]
    DIRECTION INPUT ;
    USE SIGNAL ;
    PORT
      LAYER M4 ;
        RECT  0 15.744 0.084 15.768 ;
    END
  END q2[35]
  PIN q2[36]
    DIRECTION INPUT ;
    USE SIGNAL ;
    PORT
      LAYER M4 ;
        RECT  0 15.84 0.084 15.864 ;
    END
  END q2[36]
  PIN q2[37]
    DIRECTION INPUT ;
    USE SIGNAL ;
    PORT
      LAYER M4 ;
        RECT  0 15.936 0.084 15.96 ;
    END
  END q2[37]
  PIN q2[38]
    DIRECTION INPUT ;
    USE SIGNAL ;
    PORT
      LAYER M4 ;
        RECT  0 16.08 0.084 16.104 ;
    END
  END q2[38]
  PIN q2[39]
    DIRECTION INPUT ;
    USE SIGNAL ;
    PORT
      LAYER M4 ;
        RECT  0 16.176 0.084 16.2 ;
    END
  END q2[39]
  PIN q2[3]
    DIRECTION INPUT ;
    USE SIGNAL ;
    PORT
      LAYER M4 ;
        RECT  0 12.432 0.084 12.456 ;
    END
  END q2[3]
  PIN q2[40]
    DIRECTION INPUT ;
    USE SIGNAL ;
    PORT
      LAYER M4 ;
        RECT  0 16.272 0.084 16.296 ;
    END
  END q2[40]
  PIN q2[41]
    DIRECTION INPUT ;
    USE SIGNAL ;
    PORT
      LAYER M4 ;
        RECT  0 16.368 0.084 16.392 ;
    END
  END q2[41]
  PIN q2[42]
    DIRECTION INPUT ;
    USE SIGNAL ;
    PORT
      LAYER M4 ;
        RECT  0 16.464 0.084 16.488 ;
    END
  END q2[42]
  PIN q2[43]
    DIRECTION INPUT ;
    USE SIGNAL ;
    PORT
      LAYER M4 ;
        RECT  0 16.56 0.084 16.584 ;
    END
  END q2[43]
  PIN q2[44]
    DIRECTION INPUT ;
    USE SIGNAL ;
    PORT
      LAYER M4 ;
        RECT  0 16.704 0.084 16.728 ;
    END
  END q2[44]
  PIN q2[45]
    DIRECTION INPUT ;
    USE SIGNAL ;
    PORT
      LAYER M4 ;
        RECT  0 16.8 0.084 16.824 ;
    END
  END q2[45]
  PIN q2[46]
    DIRECTION INPUT ;
    USE SIGNAL ;
    PORT
      LAYER M4 ;
        RECT  0 16.896 0.084 16.92 ;
    END
  END q2[46]
  PIN q2[47]
    DIRECTION INPUT ;
    USE SIGNAL ;
    PORT
      LAYER M4 ;
        RECT  0 16.992 0.084 17.016 ;
    END
  END q2[47]
  PIN q2[4]
    DIRECTION INPUT ;
    USE SIGNAL ;
    PORT
      LAYER M4 ;
        RECT  0 12.528 0.084 12.552 ;
    END
  END q2[4]
  PIN q2[5]
    DIRECTION INPUT ;
    USE SIGNAL ;
    PORT
      LAYER M4 ;
        RECT  0 12.624 0.084 12.648 ;
    END
  END q2[5]
  PIN q2[6]
    DIRECTION INPUT ;
    USE SIGNAL ;
    PORT
      LAYER M4 ;
        RECT  0 12.768 0.084 12.792 ;
    END
  END q2[6]
  PIN q2[7]
    DIRECTION INPUT ;
    USE SIGNAL ;
    PORT
      LAYER M4 ;
        RECT  0 12.864 0.084 12.888 ;
    END
  END q2[7]
  PIN q2[8]
    DIRECTION INPUT ;
    USE SIGNAL ;
    PORT
      LAYER M4 ;
        RECT  0 12.96 0.084 12.984 ;
    END
  END q2[8]
  PIN q2[9]
    DIRECTION INPUT ;
    USE SIGNAL ;
    PORT
      LAYER M4 ;
        RECT  0 13.056 0.084 13.08 ;
    END
  END q2[9]
  PIN q3[0]
    DIRECTION INPUT ;
    USE SIGNAL ;
    PORT
      LAYER M4 ;
        RECT  0 17.088 0.084 17.112 ;
    END
  END q3[0]
  PIN q3[10]
    DIRECTION INPUT ;
    USE SIGNAL ;
    PORT
      LAYER M4 ;
        RECT  0 18.144 0.084 18.168 ;
    END
  END q3[10]
  PIN q3[11]
    DIRECTION INPUT ;
    USE SIGNAL ;
    PORT
      LAYER M4 ;
        RECT  0 18.24 0.084 18.264 ;
    END
  END q3[11]
  PIN q3[12]
    DIRECTION INPUT ;
    USE SIGNAL ;
    PORT
      LAYER M4 ;
        RECT  0 18.336 0.084 18.36 ;
    END
  END q3[12]
  PIN q3[13]
    DIRECTION INPUT ;
    USE SIGNAL ;
    PORT
      LAYER M4 ;
        RECT  0 18.432 0.084 18.456 ;
    END
  END q3[13]
  PIN q3[14]
    DIRECTION INPUT ;
    USE SIGNAL ;
    PORT
      LAYER M4 ;
        RECT  0 18.528 0.084 18.552 ;
    END
  END q3[14]
  PIN q3[15]
    DIRECTION INPUT ;
    USE SIGNAL ;
    PORT
      LAYER M4 ;
        RECT  0 18.624 0.084 18.648 ;
    END
  END q3[15]
  PIN q3[16]
    DIRECTION INPUT ;
    USE SIGNAL ;
    PORT
      LAYER M4 ;
        RECT  0 18.768 0.084 18.792 ;
    END
  END q3[16]
  PIN q3[17]
    DIRECTION INPUT ;
    USE SIGNAL ;
    PORT
      LAYER M4 ;
        RECT  0 18.864 0.084 18.888 ;
    END
  END q3[17]
  PIN q3[18]
    DIRECTION INPUT ;
    USE SIGNAL ;
    PORT
      LAYER M4 ;
        RECT  0 18.96 0.084 18.984 ;
    END
  END q3[18]
  PIN q3[19]
    DIRECTION INPUT ;
    USE SIGNAL ;
    PORT
      LAYER M4 ;
        RECT  0 19.056 0.084 19.08 ;
    END
  END q3[19]
  PIN q3[1]
    DIRECTION INPUT ;
    USE SIGNAL ;
    PORT
      LAYER M4 ;
        RECT  0 17.184 0.084 17.208 ;
    END
  END q3[1]
  PIN q3[20]
    DIRECTION INPUT ;
    USE SIGNAL ;
    PORT
      LAYER M4 ;
        RECT  0 19.152 0.084 19.176 ;
    END
  END q3[20]
  PIN q3[21]
    DIRECTION INPUT ;
    USE SIGNAL ;
    PORT
      LAYER M4 ;
        RECT  0 19.248 0.084 19.272 ;
    END
  END q3[21]
  PIN q3[22]
    DIRECTION INPUT ;
    USE SIGNAL ;
    PORT
      LAYER M4 ;
        RECT  0 19.392 0.084 19.416 ;
    END
  END q3[22]
  PIN q3[23]
    DIRECTION INPUT ;
    USE SIGNAL ;
    PORT
      LAYER M4 ;
        RECT  0 19.488 0.084 19.512 ;
    END
  END q3[23]
  PIN q3[24]
    DIRECTION INPUT ;
    USE SIGNAL ;
    PORT
      LAYER M4 ;
        RECT  0 19.584 0.084 19.608 ;
    END
  END q3[24]
  PIN q3[25]
    DIRECTION INPUT ;
    USE SIGNAL ;
    PORT
      LAYER M4 ;
        RECT  0 19.68 0.084 19.704 ;
    END
  END q3[25]
  PIN q3[26]
    DIRECTION INPUT ;
    USE SIGNAL ;
    PORT
      LAYER M4 ;
        RECT  0 19.776 0.084 19.8 ;
    END
  END q3[26]
  PIN q3[27]
    DIRECTION INPUT ;
    USE SIGNAL ;
    PORT
      LAYER M4 ;
        RECT  0 19.872 0.084 19.896 ;
    END
  END q3[27]
  PIN q3[28]
    DIRECTION INPUT ;
    USE SIGNAL ;
    PORT
      LAYER M4 ;
        RECT  0 19.968 0.084 19.992 ;
    END
  END q3[28]
  PIN q3[29]
    DIRECTION INPUT ;
    USE SIGNAL ;
    PORT
      LAYER M4 ;
        RECT  0 20.112 0.084 20.136 ;
    END
  END q3[29]
  PIN q3[2]
    DIRECTION INPUT ;
    USE SIGNAL ;
    PORT
      LAYER M4 ;
        RECT  0 17.28 0.084 17.304 ;
    END
  END q3[2]
  PIN q3[30]
    DIRECTION INPUT ;
    USE SIGNAL ;
    PORT
      LAYER M4 ;
        RECT  0 20.208 0.084 20.232 ;
    END
  END q3[30]
  PIN q3[31]
    DIRECTION INPUT ;
    USE SIGNAL ;
    PORT
      LAYER M4 ;
        RECT  0 20.304 0.084 20.328 ;
    END
  END q3[31]
  PIN q3[32]
    DIRECTION INPUT ;
    USE SIGNAL ;
    PORT
      LAYER M4 ;
        RECT  0 20.4 0.084 20.424 ;
    END
  END q3[32]
  PIN q3[33]
    DIRECTION INPUT ;
    USE SIGNAL ;
    PORT
      LAYER M4 ;
        RECT  0 20.496 0.084 20.52 ;
    END
  END q3[33]
  PIN q3[34]
    DIRECTION INPUT ;
    USE SIGNAL ;
    PORT
      LAYER M4 ;
        RECT  0 20.592 0.084 20.616 ;
    END
  END q3[34]
  PIN q3[35]
    DIRECTION INPUT ;
    USE SIGNAL ;
    PORT
      LAYER M4 ;
        RECT  0 20.736 0.084 20.76 ;
    END
  END q3[35]
  PIN q3[36]
    DIRECTION INPUT ;
    USE SIGNAL ;
    PORT
      LAYER M4 ;
        RECT  0 20.832 0.084 20.856 ;
    END
  END q3[36]
  PIN q3[37]
    DIRECTION INPUT ;
    USE SIGNAL ;
    PORT
      LAYER M4 ;
        RECT  0 20.928 0.084 20.952 ;
    END
  END q3[37]
  PIN q3[38]
    DIRECTION INPUT ;
    USE SIGNAL ;
    PORT
      LAYER M4 ;
        RECT  0 21.024 0.084 21.048 ;
    END
  END q3[38]
  PIN q3[39]
    DIRECTION INPUT ;
    USE SIGNAL ;
    PORT
      LAYER M4 ;
        RECT  0 21.12 0.084 21.144 ;
    END
  END q3[39]
  PIN q3[3]
    DIRECTION INPUT ;
    USE SIGNAL ;
    PORT
      LAYER M4 ;
        RECT  0 17.424 0.084 17.448 ;
    END
  END q3[3]
  PIN q3[40]
    DIRECTION INPUT ;
    USE SIGNAL ;
    PORT
      LAYER M4 ;
        RECT  0 21.216 0.084 21.24 ;
    END
  END q3[40]
  PIN q3[41]
    DIRECTION INPUT ;
    USE SIGNAL ;
    PORT
      LAYER M4 ;
        RECT  0 21.312 0.084 21.336 ;
    END
  END q3[41]
  PIN q3[42]
    DIRECTION INPUT ;
    USE SIGNAL ;
    PORT
      LAYER M4 ;
        RECT  0 21.456 0.084 21.48 ;
    END
  END q3[42]
  PIN q3[43]
    DIRECTION INPUT ;
    USE SIGNAL ;
    PORT
      LAYER M4 ;
        RECT  0 21.552 0.084 21.576 ;
    END
  END q3[43]
  PIN q3[44]
    DIRECTION INPUT ;
    USE SIGNAL ;
    PORT
      LAYER M4 ;
        RECT  0 21.648 0.084 21.672 ;
    END
  END q3[44]
  PIN q3[45]
    DIRECTION INPUT ;
    USE SIGNAL ;
    PORT
      LAYER M4 ;
        RECT  0 21.744 0.084 21.768 ;
    END
  END q3[45]
  PIN q3[46]
    DIRECTION INPUT ;
    USE SIGNAL ;
    PORT
      LAYER M4 ;
        RECT  0 21.84 0.084 21.864 ;
    END
  END q3[46]
  PIN q3[47]
    DIRECTION INPUT ;
    USE SIGNAL ;
    PORT
      LAYER M4 ;
        RECT  0 21.936 0.084 21.96 ;
    END
  END q3[47]
  PIN q3[4]
    DIRECTION INPUT ;
    USE SIGNAL ;
    PORT
      LAYER M4 ;
        RECT  0 17.52 0.084 17.544 ;
    END
  END q3[4]
  PIN q3[5]
    DIRECTION INPUT ;
    USE SIGNAL ;
    PORT
      LAYER M4 ;
        RECT  0 17.616 0.084 17.64 ;
    END
  END q3[5]
  PIN q3[6]
    DIRECTION INPUT ;
    USE SIGNAL ;
    PORT
      LAYER M4 ;
        RECT  0 17.712 0.084 17.736 ;
    END
  END q3[6]
  PIN q3[7]
    DIRECTION INPUT ;
    USE SIGNAL ;
    PORT
      LAYER M4 ;
        RECT  0 17.808 0.084 17.832 ;
    END
  END q3[7]
  PIN q3[8]
    DIRECTION INPUT ;
    USE SIGNAL ;
    PORT
      LAYER M4 ;
        RECT  0 17.904 0.084 17.928 ;
    END
  END q3[8]
  PIN q3[9]
    DIRECTION INPUT ;
    USE SIGNAL ;
    PORT
      LAYER M4 ;
        RECT  0 18.048 0.084 18.072 ;
    END
  END q3[9]
  PIN q4[0]
    DIRECTION INPUT ;
    USE SIGNAL ;
    PORT
      LAYER M4 ;
        RECT  0 22.08 0.084 22.104 ;
    END
  END q4[0]
  PIN q4[10]
    DIRECTION INPUT ;
    USE SIGNAL ;
    PORT
      LAYER M4 ;
        RECT  0 23.088 0.084 23.112 ;
    END
  END q4[10]
  PIN q4[11]
    DIRECTION INPUT ;
    USE SIGNAL ;
    PORT
      LAYER M4 ;
        RECT  0 23.184 0.084 23.208 ;
    END
  END q4[11]
  PIN q4[12]
    DIRECTION INPUT ;
    USE SIGNAL ;
    PORT
      LAYER M4 ;
        RECT  0 23.28 0.084 23.304 ;
    END
  END q4[12]
  PIN q4[13]
    DIRECTION INPUT ;
    USE SIGNAL ;
    PORT
      LAYER M4 ;
        RECT  0 23.424 0.084 23.448 ;
    END
  END q4[13]
  PIN q4[14]
    DIRECTION INPUT ;
    USE SIGNAL ;
    PORT
      LAYER M4 ;
        RECT  0 23.52 0.084 23.544 ;
    END
  END q4[14]
  PIN q4[15]
    DIRECTION INPUT ;
    USE SIGNAL ;
    PORT
      LAYER M4 ;
        RECT  0 23.616 0.084 23.64 ;
    END
  END q4[15]
  PIN q4[16]
    DIRECTION INPUT ;
    USE SIGNAL ;
    PORT
      LAYER M4 ;
        RECT  0 23.712 0.084 23.736 ;
    END
  END q4[16]
  PIN q4[17]
    DIRECTION INPUT ;
    USE SIGNAL ;
    PORT
      LAYER M4 ;
        RECT  0 23.808 0.084 23.832 ;
    END
  END q4[17]
  PIN q4[18]
    DIRECTION INPUT ;
    USE SIGNAL ;
    PORT
      LAYER M4 ;
        RECT  0 23.904 0.084 23.928 ;
    END
  END q4[18]
  PIN q4[19]
    DIRECTION INPUT ;
    USE SIGNAL ;
    PORT
      LAYER M4 ;
        RECT  0 24.048 0.084 24.072 ;
    END
  END q4[19]
  PIN q4[1]
    DIRECTION INPUT ;
    USE SIGNAL ;
    PORT
      LAYER M4 ;
        RECT  0 22.176 0.084 22.2 ;
    END
  END q4[1]
  PIN q4[20]
    DIRECTION INPUT ;
    USE SIGNAL ;
    PORT
      LAYER M4 ;
        RECT  0 24.144 0.084 24.168 ;
    END
  END q4[20]
  PIN q4[21]
    DIRECTION INPUT ;
    USE SIGNAL ;
    PORT
      LAYER M4 ;
        RECT  0 24.24 0.084 24.264 ;
    END
  END q4[21]
  PIN q4[22]
    DIRECTION INPUT ;
    USE SIGNAL ;
    PORT
      LAYER M4 ;
        RECT  0 24.336 0.084 24.36 ;
    END
  END q4[22]
  PIN q4[23]
    DIRECTION INPUT ;
    USE SIGNAL ;
    PORT
      LAYER M4 ;
        RECT  0 24.432 0.084 24.456 ;
    END
  END q4[23]
  PIN q4[24]
    DIRECTION INPUT ;
    USE SIGNAL ;
    PORT
      LAYER M4 ;
        RECT  0 24.528 0.084 24.552 ;
    END
  END q4[24]
  PIN q4[25]
    DIRECTION INPUT ;
    USE SIGNAL ;
    PORT
      LAYER M4 ;
        RECT  0 24.624 0.084 24.648 ;
    END
  END q4[25]
  PIN q4[26]
    DIRECTION INPUT ;
    USE SIGNAL ;
    PORT
      LAYER M4 ;
        RECT  0 24.768 0.084 24.792 ;
    END
  END q4[26]
  PIN q4[27]
    DIRECTION INPUT ;
    USE SIGNAL ;
    PORT
      LAYER M4 ;
        RECT  0 24.864 0.084 24.888 ;
    END
  END q4[27]
  PIN q4[28]
    DIRECTION INPUT ;
    USE SIGNAL ;
    PORT
      LAYER M4 ;
        RECT  0 24.96 0.084 24.984 ;
    END
  END q4[28]
  PIN q4[29]
    DIRECTION INPUT ;
    USE SIGNAL ;
    PORT
      LAYER M4 ;
        RECT  0 25.056 0.084 25.08 ;
    END
  END q4[29]
  PIN q4[2]
    DIRECTION INPUT ;
    USE SIGNAL ;
    PORT
      LAYER M4 ;
        RECT  0 22.272 0.084 22.296 ;
    END
  END q4[2]
  PIN q4[30]
    DIRECTION INPUT ;
    USE SIGNAL ;
    PORT
      LAYER M4 ;
        RECT  0 25.152 0.084 25.176 ;
    END
  END q4[30]
  PIN q4[31]
    DIRECTION INPUT ;
    USE SIGNAL ;
    PORT
      LAYER M4 ;
        RECT  0 25.248 0.084 25.272 ;
    END
  END q4[31]
  PIN q4[32]
    DIRECTION INPUT ;
    USE SIGNAL ;
    PORT
      LAYER M4 ;
        RECT  0 25.392 0.084 25.416 ;
    END
  END q4[32]
  PIN q4[33]
    DIRECTION INPUT ;
    USE SIGNAL ;
    PORT
      LAYER M4 ;
        RECT  0 25.488 0.084 25.512 ;
    END
  END q4[33]
  PIN q4[34]
    DIRECTION INPUT ;
    USE SIGNAL ;
    PORT
      LAYER M4 ;
        RECT  0 25.584 0.084 25.608 ;
    END
  END q4[34]
  PIN q4[35]
    DIRECTION INPUT ;
    USE SIGNAL ;
    PORT
      LAYER M4 ;
        RECT  0 25.68 0.084 25.704 ;
    END
  END q4[35]
  PIN q4[36]
    DIRECTION INPUT ;
    USE SIGNAL ;
    PORT
      LAYER M4 ;
        RECT  0 25.776 0.084 25.8 ;
    END
  END q4[36]
  PIN q4[37]
    DIRECTION INPUT ;
    USE SIGNAL ;
    PORT
      LAYER M4 ;
        RECT  0 25.872 0.084 25.896 ;
    END
  END q4[37]
  PIN q4[38]
    DIRECTION INPUT ;
    USE SIGNAL ;
    PORT
      LAYER M4 ;
        RECT  0 25.968 0.084 25.992 ;
    END
  END q4[38]
  PIN q4[39]
    DIRECTION INPUT ;
    USE SIGNAL ;
    PORT
      LAYER M4 ;
        RECT  0 26.112 0.084 26.136 ;
    END
  END q4[39]
  PIN q4[3]
    DIRECTION INPUT ;
    USE SIGNAL ;
    PORT
      LAYER M4 ;
        RECT  0 22.368 0.084 22.392 ;
    END
  END q4[3]
  PIN q4[40]
    DIRECTION INPUT ;
    USE SIGNAL ;
    PORT
      LAYER M4 ;
        RECT  0 26.208 0.084 26.232 ;
    END
  END q4[40]
  PIN q4[41]
    DIRECTION INPUT ;
    USE SIGNAL ;
    PORT
      LAYER M4 ;
        RECT  0 26.304 0.084 26.328 ;
    END
  END q4[41]
  PIN q4[42]
    DIRECTION INPUT ;
    USE SIGNAL ;
    PORT
      LAYER M4 ;
        RECT  0 26.4 0.084 26.424 ;
    END
  END q4[42]
  PIN q4[43]
    DIRECTION INPUT ;
    USE SIGNAL ;
    PORT
      LAYER M4 ;
        RECT  0 26.496 0.084 26.52 ;
    END
  END q4[43]
  PIN q4[44]
    DIRECTION INPUT ;
    USE SIGNAL ;
    PORT
      LAYER M4 ;
        RECT  0 26.592 0.084 26.616 ;
    END
  END q4[44]
  PIN q4[45]
    DIRECTION INPUT ;
    USE SIGNAL ;
    PORT
      LAYER M4 ;
        RECT  0 26.736 0.084 26.76 ;
    END
  END q4[45]
  PIN q4[46]
    DIRECTION INPUT ;
    USE SIGNAL ;
    PORT
      LAYER M4 ;
        RECT  0 26.832 0.084 26.856 ;
    END
  END q4[46]
  PIN q4[47]
    DIRECTION INPUT ;
    USE SIGNAL ;
    PORT
      LAYER M4 ;
        RECT  0 26.928 0.084 26.952 ;
    END
  END q4[47]
  PIN q4[4]
    DIRECTION INPUT ;
    USE SIGNAL ;
    PORT
      LAYER M4 ;
        RECT  0 22.464 0.084 22.488 ;
    END
  END q4[4]
  PIN q4[5]
    DIRECTION INPUT ;
    USE SIGNAL ;
    PORT
      LAYER M4 ;
        RECT  0 22.56 0.084 22.584 ;
    END
  END q4[5]
  PIN q4[6]
    DIRECTION INPUT ;
    USE SIGNAL ;
    PORT
      LAYER M4 ;
        RECT  0 22.704 0.084 22.728 ;
    END
  END q4[6]
  PIN q4[7]
    DIRECTION INPUT ;
    USE SIGNAL ;
    PORT
      LAYER M4 ;
        RECT  0 22.8 0.084 22.824 ;
    END
  END q4[7]
  PIN q4[8]
    DIRECTION INPUT ;
    USE SIGNAL ;
    PORT
      LAYER M4 ;
        RECT  0 22.896 0.084 22.92 ;
    END
  END q4[8]
  PIN q4[9]
    DIRECTION INPUT ;
    USE SIGNAL ;
    PORT
      LAYER M4 ;
        RECT  0 22.992 0.084 23.016 ;
    END
  END q4[9]
  PIN q5[0]
    DIRECTION INPUT ;
    USE SIGNAL ;
    PORT
      LAYER M4 ;
        RECT  0 27.024 0.084 27.048 ;
    END
  END q5[0]
  PIN q5[10]
    DIRECTION INPUT ;
    USE SIGNAL ;
    PORT
      LAYER M4 ;
        RECT  0 28.08 0.084 28.104 ;
    END
  END q5[10]
  PIN q5[11]
    DIRECTION INPUT ;
    USE SIGNAL ;
    PORT
      LAYER M4 ;
        RECT  0 28.176 0.084 28.2 ;
    END
  END q5[11]
  PIN q5[12]
    DIRECTION INPUT ;
    USE SIGNAL ;
    PORT
      LAYER M4 ;
        RECT  0 28.272 0.084 28.296 ;
    END
  END q5[12]
  PIN q5[13]
    DIRECTION INPUT ;
    USE SIGNAL ;
    PORT
      LAYER M4 ;
        RECT  0 28.368 0.084 28.392 ;
    END
  END q5[13]
  PIN q5[14]
    DIRECTION INPUT ;
    USE SIGNAL ;
    PORT
      LAYER M4 ;
        RECT  0 28.464 0.084 28.488 ;
    END
  END q5[14]
  PIN q5[15]
    DIRECTION INPUT ;
    USE SIGNAL ;
    PORT
      LAYER M4 ;
        RECT  0 28.56 0.084 28.584 ;
    END
  END q5[15]
  PIN q5[16]
    DIRECTION INPUT ;
    USE SIGNAL ;
    PORT
      LAYER M4 ;
        RECT  0 28.656 0.084 28.68 ;
    END
  END q5[16]
  PIN q5[17]
    DIRECTION INPUT ;
    USE SIGNAL ;
    PORT
      LAYER M4 ;
        RECT  0 28.8 0.084 28.824 ;
    END
  END q5[17]
  PIN q5[18]
    DIRECTION INPUT ;
    USE SIGNAL ;
    PORT
      LAYER M4 ;
        RECT  0 28.896 0.084 28.92 ;
    END
  END q5[18]
  PIN q5[19]
    DIRECTION INPUT ;
    USE SIGNAL ;
    PORT
      LAYER M4 ;
        RECT  0 28.992 0.084 29.016 ;
    END
  END q5[19]
  PIN q5[1]
    DIRECTION INPUT ;
    USE SIGNAL ;
    PORT
      LAYER M4 ;
        RECT  0 27.12 0.084 27.144 ;
    END
  END q5[1]
  PIN q5[20]
    DIRECTION INPUT ;
    USE SIGNAL ;
    PORT
      LAYER M4 ;
        RECT  0 29.088 0.084 29.112 ;
    END
  END q5[20]
  PIN q5[21]
    DIRECTION INPUT ;
    USE SIGNAL ;
    PORT
      LAYER M4 ;
        RECT  0 29.184 0.084 29.208 ;
    END
  END q5[21]
  PIN q5[22]
    DIRECTION INPUT ;
    USE SIGNAL ;
    PORT
      LAYER M4 ;
        RECT  0 29.28 0.084 29.304 ;
    END
  END q5[22]
  PIN q5[23]
    DIRECTION INPUT ;
    USE SIGNAL ;
    PORT
      LAYER M4 ;
        RECT  0 29.424 0.084 29.448 ;
    END
  END q5[23]
  PIN q5[24]
    DIRECTION INPUT ;
    USE SIGNAL ;
    PORT
      LAYER M4 ;
        RECT  0 29.52 0.084 29.544 ;
    END
  END q5[24]
  PIN q5[25]
    DIRECTION INPUT ;
    USE SIGNAL ;
    PORT
      LAYER M4 ;
        RECT  0 29.616 0.084 29.64 ;
    END
  END q5[25]
  PIN q5[26]
    DIRECTION INPUT ;
    USE SIGNAL ;
    PORT
      LAYER M4 ;
        RECT  0 29.712 0.084 29.736 ;
    END
  END q5[26]
  PIN q5[27]
    DIRECTION INPUT ;
    USE SIGNAL ;
    PORT
      LAYER M4 ;
        RECT  0 29.808 0.084 29.832 ;
    END
  END q5[27]
  PIN q5[28]
    DIRECTION INPUT ;
    USE SIGNAL ;
    PORT
      LAYER M4 ;
        RECT  0 29.904 0.084 29.928 ;
    END
  END q5[28]
  PIN q5[29]
    DIRECTION INPUT ;
    USE SIGNAL ;
    PORT
      LAYER M4 ;
        RECT  0 30.048 0.084 30.072 ;
    END
  END q5[29]
  PIN q5[2]
    DIRECTION INPUT ;
    USE SIGNAL ;
    PORT
      LAYER M4 ;
        RECT  0 27.216 0.084 27.24 ;
    END
  END q5[2]
  PIN q5[30]
    DIRECTION INPUT ;
    USE SIGNAL ;
    PORT
      LAYER M4 ;
        RECT  0 30.144 0.084 30.168 ;
    END
  END q5[30]
  PIN q5[31]
    DIRECTION INPUT ;
    USE SIGNAL ;
    PORT
      LAYER M4 ;
        RECT  0 30.24 0.084 30.264 ;
    END
  END q5[31]
  PIN q5[32]
    DIRECTION INPUT ;
    USE SIGNAL ;
    PORT
      LAYER M4 ;
        RECT  0 30.336 0.084 30.36 ;
    END
  END q5[32]
  PIN q5[33]
    DIRECTION INPUT ;
    USE SIGNAL ;
    PORT
      LAYER M4 ;
        RECT  0 30.432 0.084 30.456 ;
    END
  END q5[33]
  PIN q5[34]
    DIRECTION INPUT ;
    USE SIGNAL ;
    PORT
      LAYER M4 ;
        RECT  0 30.528 0.084 30.552 ;
    END
  END q5[34]
  PIN q5[35]
    DIRECTION INPUT ;
    USE SIGNAL ;
    PORT
      LAYER M4 ;
        RECT  0 30.624 0.084 30.648 ;
    END
  END q5[35]
  PIN q5[36]
    DIRECTION INPUT ;
    USE SIGNAL ;
    PORT
      LAYER M4 ;
        RECT  0 30.768 0.084 30.792 ;
    END
  END q5[36]
  PIN q5[37]
    DIRECTION INPUT ;
    USE SIGNAL ;
    PORT
      LAYER M4 ;
        RECT  0 30.864 0.084 30.888 ;
    END
  END q5[37]
  PIN q5[38]
    DIRECTION INPUT ;
    USE SIGNAL ;
    PORT
      LAYER M4 ;
        RECT  0 30.96 0.084 30.984 ;
    END
  END q5[38]
  PIN q5[39]
    DIRECTION INPUT ;
    USE SIGNAL ;
    PORT
      LAYER M4 ;
        RECT  0 31.056 0.084 31.08 ;
    END
  END q5[39]
  PIN q5[3]
    DIRECTION INPUT ;
    USE SIGNAL ;
    PORT
      LAYER M4 ;
        RECT  0 27.312 0.084 27.336 ;
    END
  END q5[3]
  PIN q5[40]
    DIRECTION INPUT ;
    USE SIGNAL ;
    PORT
      LAYER M4 ;
        RECT  0 31.152 0.084 31.176 ;
    END
  END q5[40]
  PIN q5[41]
    DIRECTION INPUT ;
    USE SIGNAL ;
    PORT
      LAYER M4 ;
        RECT  0 31.248 0.084 31.272 ;
    END
  END q5[41]
  PIN q5[42]
    DIRECTION INPUT ;
    USE SIGNAL ;
    PORT
      LAYER M4 ;
        RECT  0 31.392 0.084 31.416 ;
    END
  END q5[42]
  PIN q5[43]
    DIRECTION INPUT ;
    USE SIGNAL ;
    PORT
      LAYER M4 ;
        RECT  0 31.488 0.084 31.512 ;
    END
  END q5[43]
  PIN q5[44]
    DIRECTION INPUT ;
    USE SIGNAL ;
    PORT
      LAYER M4 ;
        RECT  0 31.584 0.084 31.608 ;
    END
  END q5[44]
  PIN q5[45]
    DIRECTION INPUT ;
    USE SIGNAL ;
    PORT
      LAYER M4 ;
        RECT  0 31.68 0.084 31.704 ;
    END
  END q5[45]
  PIN q5[46]
    DIRECTION INPUT ;
    USE SIGNAL ;
    PORT
      LAYER M4 ;
        RECT  0 31.776 0.084 31.8 ;
    END
  END q5[46]
  PIN q5[47]
    DIRECTION INPUT ;
    USE SIGNAL ;
    PORT
      LAYER M4 ;
        RECT  0 31.872 0.084 31.896 ;
    END
  END q5[47]
  PIN q5[4]
    DIRECTION INPUT ;
    USE SIGNAL ;
    PORT
      LAYER M4 ;
        RECT  0 27.456 0.084 27.48 ;
    END
  END q5[4]
  PIN q5[5]
    DIRECTION INPUT ;
    USE SIGNAL ;
    PORT
      LAYER M4 ;
        RECT  0 27.552 0.084 27.576 ;
    END
  END q5[5]
  PIN q5[6]
    DIRECTION INPUT ;
    USE SIGNAL ;
    PORT
      LAYER M4 ;
        RECT  0 27.648 0.084 27.672 ;
    END
  END q5[6]
  PIN q5[7]
    DIRECTION INPUT ;
    USE SIGNAL ;
    PORT
      LAYER M4 ;
        RECT  0 27.744 0.084 27.768 ;
    END
  END q5[7]
  PIN q5[8]
    DIRECTION INPUT ;
    USE SIGNAL ;
    PORT
      LAYER M4 ;
        RECT  0 27.84 0.084 27.864 ;
    END
  END q5[8]
  PIN q5[9]
    DIRECTION INPUT ;
    USE SIGNAL ;
    PORT
      LAYER M4 ;
        RECT  0 27.936 0.084 27.96 ;
    END
  END q5[9]
  PIN q6[0]
    DIRECTION INPUT ;
    USE SIGNAL ;
    PORT
      LAYER M4 ;
        RECT  0 31.968 0.084 31.992 ;
    END
  END q6[0]
  PIN q6[10]
    DIRECTION INPUT ;
    USE SIGNAL ;
    PORT
      LAYER M4 ;
        RECT  0 33.024 0.084 33.048 ;
    END
  END q6[10]
  PIN q6[11]
    DIRECTION INPUT ;
    USE SIGNAL ;
    PORT
      LAYER M4 ;
        RECT  0 33.12 0.084 33.144 ;
    END
  END q6[11]
  PIN q6[12]
    DIRECTION INPUT ;
    USE SIGNAL ;
    PORT
      LAYER M4 ;
        RECT  0 33.216 0.084 33.24 ;
    END
  END q6[12]
  PIN q6[13]
    DIRECTION INPUT ;
    USE SIGNAL ;
    PORT
      LAYER M4 ;
        RECT  0 33.312 0.084 33.336 ;
    END
  END q6[13]
  PIN q6[14]
    DIRECTION INPUT ;
    USE SIGNAL ;
    PORT
      LAYER M4 ;
        RECT  0 33.456 0.084 33.48 ;
    END
  END q6[14]
  PIN q6[15]
    DIRECTION INPUT ;
    USE SIGNAL ;
    PORT
      LAYER M4 ;
        RECT  0 33.552 0.084 33.576 ;
    END
  END q6[15]
  PIN q6[16]
    DIRECTION INPUT ;
    USE SIGNAL ;
    PORT
      LAYER M4 ;
        RECT  0 33.648 0.084 33.672 ;
    END
  END q6[16]
  PIN q6[17]
    DIRECTION INPUT ;
    USE SIGNAL ;
    PORT
      LAYER M4 ;
        RECT  0 33.744 0.084 33.768 ;
    END
  END q6[17]
  PIN q6[18]
    DIRECTION INPUT ;
    USE SIGNAL ;
    PORT
      LAYER M4 ;
        RECT  0 33.84 0.084 33.864 ;
    END
  END q6[18]
  PIN q6[19]
    DIRECTION INPUT ;
    USE SIGNAL ;
    PORT
      LAYER M4 ;
        RECT  0 33.936 0.084 33.96 ;
    END
  END q6[19]
  PIN q6[1]
    DIRECTION INPUT ;
    USE SIGNAL ;
    PORT
      LAYER M4 ;
        RECT  0 32.112 0.084 32.136 ;
    END
  END q6[1]
  PIN q6[20]
    DIRECTION INPUT ;
    USE SIGNAL ;
    PORT
      LAYER M4 ;
        RECT  0 34.08 0.084 34.104 ;
    END
  END q6[20]
  PIN q6[21]
    DIRECTION INPUT ;
    USE SIGNAL ;
    PORT
      LAYER M4 ;
        RECT  0 34.176 0.084 34.2 ;
    END
  END q6[21]
  PIN q6[22]
    DIRECTION INPUT ;
    USE SIGNAL ;
    PORT
      LAYER M4 ;
        RECT  0 34.272 0.084 34.296 ;
    END
  END q6[22]
  PIN q6[23]
    DIRECTION INPUT ;
    USE SIGNAL ;
    PORT
      LAYER M4 ;
        RECT  0 34.368 0.084 34.392 ;
    END
  END q6[23]
  PIN q6[24]
    DIRECTION INPUT ;
    USE SIGNAL ;
    PORT
      LAYER M4 ;
        RECT  0 34.464 0.084 34.488 ;
    END
  END q6[24]
  PIN q6[25]
    DIRECTION INPUT ;
    USE SIGNAL ;
    PORT
      LAYER M4 ;
        RECT  0 34.56 0.084 34.584 ;
    END
  END q6[25]
  PIN q6[26]
    DIRECTION INPUT ;
    USE SIGNAL ;
    PORT
      LAYER M4 ;
        RECT  0 34.656 0.084 34.68 ;
    END
  END q6[26]
  PIN q6[27]
    DIRECTION INPUT ;
    USE SIGNAL ;
    PORT
      LAYER M4 ;
        RECT  0 34.8 0.084 34.824 ;
    END
  END q6[27]
  PIN q6[28]
    DIRECTION INPUT ;
    USE SIGNAL ;
    PORT
      LAYER M4 ;
        RECT  0 34.896 0.084 34.92 ;
    END
  END q6[28]
  PIN q6[29]
    DIRECTION INPUT ;
    USE SIGNAL ;
    PORT
      LAYER M4 ;
        RECT  0 34.992 0.084 35.016 ;
    END
  END q6[29]
  PIN q6[2]
    DIRECTION INPUT ;
    USE SIGNAL ;
    PORT
      LAYER M4 ;
        RECT  0 32.208 0.084 32.232 ;
    END
  END q6[2]
  PIN q6[30]
    DIRECTION INPUT ;
    USE SIGNAL ;
    PORT
      LAYER M4 ;
        RECT  0 35.088 0.084 35.112 ;
    END
  END q6[30]
  PIN q6[31]
    DIRECTION INPUT ;
    USE SIGNAL ;
    PORT
      LAYER M4 ;
        RECT  0 35.184 0.084 35.208 ;
    END
  END q6[31]
  PIN q6[32]
    DIRECTION INPUT ;
    USE SIGNAL ;
    PORT
      LAYER M4 ;
        RECT  0 35.28 0.084 35.304 ;
    END
  END q6[32]
  PIN q6[33]
    DIRECTION INPUT ;
    USE SIGNAL ;
    PORT
      LAYER M4 ;
        RECT  0 35.424 0.084 35.448 ;
    END
  END q6[33]
  PIN q6[34]
    DIRECTION INPUT ;
    USE SIGNAL ;
    PORT
      LAYER M4 ;
        RECT  0 35.52 0.084 35.544 ;
    END
  END q6[34]
  PIN q6[35]
    DIRECTION INPUT ;
    USE SIGNAL ;
    PORT
      LAYER M4 ;
        RECT  0 35.616 0.084 35.64 ;
    END
  END q6[35]
  PIN q6[36]
    DIRECTION INPUT ;
    USE SIGNAL ;
    PORT
      LAYER M4 ;
        RECT  0 35.712 0.084 35.736 ;
    END
  END q6[36]
  PIN q6[37]
    DIRECTION INPUT ;
    USE SIGNAL ;
    PORT
      LAYER M4 ;
        RECT  0 35.808 0.084 35.832 ;
    END
  END q6[37]
  PIN q6[38]
    DIRECTION INPUT ;
    USE SIGNAL ;
    PORT
      LAYER M4 ;
        RECT  0 35.904 0.084 35.928 ;
    END
  END q6[38]
  PIN q6[39]
    DIRECTION INPUT ;
    USE SIGNAL ;
    PORT
      LAYER M4 ;
        RECT  0 36 0.084 36.024 ;
    END
  END q6[39]
  PIN q6[3]
    DIRECTION INPUT ;
    USE SIGNAL ;
    PORT
      LAYER M4 ;
        RECT  0 32.304 0.084 32.328 ;
    END
  END q6[3]
  PIN q6[40]
    DIRECTION INPUT ;
    USE SIGNAL ;
    PORT
      LAYER M4 ;
        RECT  0 36.144 0.084 36.168 ;
    END
  END q6[40]
  PIN q6[41]
    DIRECTION INPUT ;
    USE SIGNAL ;
    PORT
      LAYER M4 ;
        RECT  0 36.24 0.084 36.264 ;
    END
  END q6[41]
  PIN q6[42]
    DIRECTION INPUT ;
    USE SIGNAL ;
    PORT
      LAYER M4 ;
        RECT  0 36.336 0.084 36.36 ;
    END
  END q6[42]
  PIN q6[43]
    DIRECTION INPUT ;
    USE SIGNAL ;
    PORT
      LAYER M4 ;
        RECT  0 36.432 0.084 36.456 ;
    END
  END q6[43]
  PIN q6[44]
    DIRECTION INPUT ;
    USE SIGNAL ;
    PORT
      LAYER M4 ;
        RECT  0 36.528 0.084 36.552 ;
    END
  END q6[44]
  PIN q6[45]
    DIRECTION INPUT ;
    USE SIGNAL ;
    PORT
      LAYER M4 ;
        RECT  0 36.624 0.084 36.648 ;
    END
  END q6[45]
  PIN q6[46]
    DIRECTION INPUT ;
    USE SIGNAL ;
    PORT
      LAYER M4 ;
        RECT  0 36.768 0.084 36.792 ;
    END
  END q6[46]
  PIN q6[47]
    DIRECTION INPUT ;
    USE SIGNAL ;
    PORT
      LAYER M4 ;
        RECT  0 36.864 0.084 36.888 ;
    END
  END q6[47]
  PIN q6[4]
    DIRECTION INPUT ;
    USE SIGNAL ;
    PORT
      LAYER M4 ;
        RECT  0 32.4 0.084 32.424 ;
    END
  END q6[4]
  PIN q6[5]
    DIRECTION INPUT ;
    USE SIGNAL ;
    PORT
      LAYER M4 ;
        RECT  0 32.496 0.084 32.52 ;
    END
  END q6[5]
  PIN q6[6]
    DIRECTION INPUT ;
    USE SIGNAL ;
    PORT
      LAYER M4 ;
        RECT  0 32.592 0.084 32.616 ;
    END
  END q6[6]
  PIN q6[7]
    DIRECTION INPUT ;
    USE SIGNAL ;
    PORT
      LAYER M4 ;
        RECT  0 32.736 0.084 32.76 ;
    END
  END q6[7]
  PIN q6[8]
    DIRECTION INPUT ;
    USE SIGNAL ;
    PORT
      LAYER M4 ;
        RECT  0 32.832 0.084 32.856 ;
    END
  END q6[8]
  PIN q6[9]
    DIRECTION INPUT ;
    USE SIGNAL ;
    PORT
      LAYER M4 ;
        RECT  0 32.928 0.084 32.952 ;
    END
  END q6[9]
  PIN rst_n[0]
    DIRECTION INPUT ;
    USE SIGNAL ;
    PORT
      LAYER M5 ;
        RECT  8.736 0 8.76 0.084 ;
    END
  END rst_n[0]
  PIN st[0]
    DIRECTION OUTPUT ;
    USE SIGNAL ;
    PORT
      LAYER M4 ;
        RECT  17.196 35.616 17.28 35.64 ;
    END
    PORT
      LAYER M4 ;
        RECT  15.361 35.616 17.244 35.64 ;
    END
  END st[0]
  PIN st[1]
    DIRECTION OUTPUT ;
    USE SIGNAL ;
    PORT
      LAYER M4 ;
        RECT  17.196 37.776 17.28 37.8 ;
    END
    PORT
      LAYER M4 ;
        RECT  16.477 37.776 17.244 37.8 ;
    END
  END st[1]
  PIN VDD
    DIRECTION INOUT ;
    USE POWER ;
    PORT
      LAYER M5 ;
        RECT  13.392 2.151 13.512 38.889 ;
        RECT  10.692 2.151 10.812 38.889 ;
        RECT  7.992 2.151 8.112 38.889 ;
        RECT  5.292 2.151 5.412 38.889 ;
        RECT  2.592 2.151 2.712 38.889 ;
    END
  END VDD
  PIN VSS
    DIRECTION INOUT ;
    USE GROUND ;
    PORT
      LAYER M5 ;
        RECT  13.2 2.137 13.32 38.903 ;
        RECT  10.5 2.137 10.62 38.903 ;
        RECT  7.8 2.137 7.92 38.903 ;
        RECT  5.1 2.137 5.22 38.903 ;
        RECT  2.4 2.137 2.52 38.903 ;
    END
  END VSS
  # OT_OBS_CLOSED layer=M5 d_um=1.536 added=30
  OBS
    LAYER RVTN ;
     RECT  2.16 2.16 15.12 2.295 ;
     RECT  2.16 2.565 15.12 2.835 ;
     RECT  2.16 3.105 15.12 3.375 ;
     RECT  2.16 3.645 15.12 3.915 ;
     RECT  2.16 4.185 15.12 4.455 ;
     RECT  2.16 4.725 15.12 4.995 ;
     RECT  2.16 5.265 15.12 5.535 ;
     RECT  2.16 5.805 15.12 6.075 ;
     RECT  2.16 6.345 15.12 6.615 ;
     RECT  2.16 6.885 15.12 7.155 ;
     RECT  2.16 7.425 15.12 7.695 ;
     RECT  2.16 7.965 15.12 8.235 ;
     RECT  2.16 8.505 15.12 8.775 ;
     RECT  2.16 9.045 15.12 9.315 ;
     RECT  2.16 9.585 15.12 9.855 ;
     RECT  2.16 10.125 15.12 10.395 ;
     RECT  2.16 10.665 15.12 10.935 ;
     RECT  2.16 11.205 15.12 11.475 ;
     RECT  2.16 11.745 15.12 12.015 ;
     RECT  2.16 12.285 15.12 12.555 ;
     RECT  2.16 12.825 15.12 13.095 ;
     RECT  2.16 13.365 15.12 13.635 ;
     RECT  2.16 13.905 15.12 14.175 ;
     RECT  2.16 14.445 15.12 14.715 ;
     RECT  2.16 14.985 15.12 15.255 ;
     RECT  2.16 15.525 15.12 15.795 ;
     RECT  2.16 16.065 15.12 16.335 ;
     RECT  2.16 16.605 15.12 16.875 ;
     RECT  2.16 17.145 15.12 17.415 ;
     RECT  2.16 17.685 15.12 17.955 ;
     RECT  2.16 18.225 15.12 18.495 ;
     RECT  2.16 18.765 15.12 19.035 ;
     RECT  2.16 19.305 15.12 19.575 ;
     RECT  2.16 19.845 15.12 20.115 ;
     RECT  2.16 20.385 15.12 20.655 ;
     RECT  2.16 20.925 15.12 21.195 ;
     RECT  2.16 21.465 15.12 21.735 ;
     RECT  2.16 22.005 15.12 22.275 ;
     RECT  2.16 22.545 15.12 22.815 ;
     RECT  2.16 23.085 15.12 23.355 ;
     RECT  2.16 23.625 15.12 23.895 ;
     RECT  2.16 24.165 15.12 24.435 ;
     RECT  2.16 24.705 15.12 24.975 ;
     RECT  2.16 25.245 15.12 25.515 ;
     RECT  2.16 25.785 15.12 26.055 ;
     RECT  2.16 26.325 15.12 26.595 ;
     RECT  2.16 26.865 15.12 27.135 ;
     RECT  2.16 27.405 15.12 27.675 ;
     RECT  2.16 27.945 15.12 28.215 ;
     RECT  2.16 28.485 15.12 28.755 ;
     RECT  2.16 29.025 15.12 29.295 ;
     RECT  2.16 29.565 15.12 29.835 ;
     RECT  2.16 30.105 15.12 30.375 ;
     RECT  2.16 30.645 15.12 30.915 ;
     RECT  2.16 31.185 15.12 31.455 ;
     RECT  2.16 31.725 15.12 31.995 ;
     RECT  2.16 32.265 15.12 32.535 ;
     RECT  2.16 32.805 15.12 33.075 ;
     RECT  2.16 33.345 15.12 33.615 ;
     RECT  2.16 33.885 15.12 34.155 ;
     RECT  2.16 34.425 15.12 34.695 ;
     RECT  2.16 34.965 15.12 35.235 ;
     RECT  2.16 35.505 15.12 35.775 ;
     RECT  2.16 36.045 15.12 36.315 ;
     RECT  2.16 36.585 15.12 36.855 ;
     RECT  2.16 37.125 15.12 37.395 ;
     RECT  2.16 37.665 15.12 37.935 ;
     RECT  2.16 38.205 15.12 38.475 ;
     RECT  2.16 38.745 15.12 38.88 ;
    LAYER RVTP ;
     RECT  2.16 2.295 15.12 2.565 ;
     RECT  2.16 2.835 15.12 3.105 ;
     RECT  2.16 3.375 15.12 3.645 ;
     RECT  2.16 3.915 15.12 4.185 ;
     RECT  2.16 4.455 15.12 4.725 ;
     RECT  2.16 4.995 15.12 5.265 ;
     RECT  2.16 5.535 15.12 5.805 ;
     RECT  2.16 6.075 15.12 6.345 ;
     RECT  2.16 6.615 15.12 6.885 ;
     RECT  2.16 7.155 15.12 7.425 ;
     RECT  2.16 7.695 15.12 7.965 ;
     RECT  2.16 8.235 15.12 8.505 ;
     RECT  2.16 8.775 15.12 9.045 ;
     RECT  2.16 9.315 15.12 9.585 ;
     RECT  2.16 9.855 15.12 10.125 ;
     RECT  2.16 10.395 15.12 10.665 ;
     RECT  2.16 10.935 15.12 11.205 ;
     RECT  2.16 11.475 15.12 11.745 ;
     RECT  2.16 12.015 15.12 12.285 ;
     RECT  2.16 12.555 15.12 12.825 ;
     RECT  2.16 13.095 15.12 13.365 ;
     RECT  2.16 13.635 15.12 13.905 ;
     RECT  2.16 14.175 15.12 14.445 ;
     RECT  2.16 14.715 15.12 14.985 ;
     RECT  2.16 15.255 15.12 15.525 ;
     RECT  2.16 15.795 15.12 16.065 ;
     RECT  2.16 16.335 15.12 16.605 ;
     RECT  2.16 16.875 15.12 17.145 ;
     RECT  2.16 17.415 15.12 17.685 ;
     RECT  2.16 17.955 15.12 18.225 ;
     RECT  2.16 18.495 15.12 18.765 ;
     RECT  2.16 19.035 15.12 19.305 ;
     RECT  2.16 19.575 15.12 19.845 ;
     RECT  2.16 20.115 15.12 20.385 ;
     RECT  2.16 20.655 15.12 20.925 ;
     RECT  2.16 21.195 15.12 21.465 ;
     RECT  2.16 21.735 15.12 22.005 ;
     RECT  2.16 22.275 15.12 22.545 ;
     RECT  2.16 22.815 15.12 23.085 ;
     RECT  2.16 23.355 15.12 23.625 ;
     RECT  2.16 23.895 15.12 24.165 ;
     RECT  2.16 24.435 15.12 24.705 ;
     RECT  2.16 24.975 15.12 25.245 ;
     RECT  2.16 25.515 15.12 25.785 ;
     RECT  2.16 26.055 15.12 26.325 ;
     RECT  2.16 26.595 15.12 26.865 ;
     RECT  2.16 27.135 15.12 27.405 ;
     RECT  2.16 27.675 15.12 27.945 ;
     RECT  2.16 28.215 15.12 28.485 ;
     RECT  2.16 28.755 15.12 29.025 ;
     RECT  2.16 29.295 15.12 29.565 ;
     RECT  2.16 29.835 15.12 30.105 ;
     RECT  2.16 30.375 15.12 30.645 ;
     RECT  2.16 30.915 15.12 31.185 ;
     RECT  2.16 31.455 15.12 31.725 ;
     RECT  2.16 31.995 15.12 32.265 ;
     RECT  2.16 32.535 15.12 32.805 ;
     RECT  2.16 33.075 15.12 33.345 ;
     RECT  2.16 33.615 15.12 33.885 ;
     RECT  2.16 34.155 15.12 34.425 ;
     RECT  2.16 34.695 15.12 34.965 ;
     RECT  2.16 35.235 15.12 35.505 ;
     RECT  2.16 35.775 15.12 36.045 ;
     RECT  2.16 36.315 15.12 36.585 ;
     RECT  2.16 36.855 15.12 37.125 ;
     RECT  2.16 37.395 15.12 37.665 ;
     RECT  2.16 37.935 15.12 38.205 ;
     RECT  2.16 38.475 15.12 38.745 ;
    LAYER M1 ;
     RECT  2.16 2.151 15.12 38.889 ;
    LAYER M2 ;
     RECT  0.031 13.176 0.067 13.194 ;
     RECT  0.031 22.716 0.067 22.734 ;
     RECT  0.031 35.361 0.067 35.379 ;
     RECT  0.031 16.236 0.103 16.254 ;
     RECT  0.031 17.154 0.103 17.172 ;
     RECT  0.067 26.181 0.103 26.199 ;
     RECT  0.031 28.458 0.103 28.476 ;
     RECT  0.031 30.852 0.103 30.87 ;
     RECT  0.103 16.236 0.131 17.172 ;
     RECT  0.103 23.904 0.139 23.922 ;
     RECT  0.103 30.852 0.139 30.978 ;
     RECT  0.103 32.472 0.139 32.49 ;
     RECT  0.067 35.361 0.139 35.424 ;
     RECT  0.139 35.361 0.167 36.144 ;
     RECT  0.139 23.706 0.175 23.922 ;
     RECT  0.103 24.948 0.175 26.199 ;
     RECT  0.103 27.342 0.175 29.628 ;
     RECT  0.139 30.726 0.175 30.978 ;
     RECT  0.103 4.041 0.203 4.176 ;
     RECT  0.103 6.048 0.203 6.3 ;
     RECT  0.103 9.36 0.203 9.378 ;
     RECT  0.067 13.176 0.211 13.32 ;
     RECT  0.103 33.93 0.211 34.488 ;
     RECT  0.139 5.076 0.239 5.094 ;
     RECT  0.131 16.236 0.239 17.1 ;
     RECT  0.167 35.856 0.239 36.144 ;
     RECT  0.175 11.484 0.283 11.502 ;
     RECT  0.239 16.344 0.347 17.1 ;
     RECT  0.211 13.104 0.355 13.32 ;
     RECT  0.247 14.724 0.499 14.742 ;
     RECT  0.175 27.342 0.499 31.14 ;
     RECT  0.283 11.214 0.535 11.502 ;
     RECT  0.499 18.972 0.535 18.99 ;
     RECT  0.067 22.716 0.535 22.914 ;
     RECT  0.175 23.706 0.535 26.199 ;
     RECT  0.139 32.04 0.535 32.49 ;
     RECT  0.211 33.93 0.535 34.956 ;
     RECT  0.535 18.972 0.787 19.26 ;
     RECT  0.103 8.586 0.823 8.604 ;
     RECT  0.535 22.716 0.859 26.199 ;
     RECT  0.535 11.214 0.895 11.97 ;
     RECT  0.355 13.104 0.895 13.392 ;
     RECT  0.347 17.082 0.959 17.1 ;
     RECT  0.499 14.724 0.967 15.012 ;
     RECT  0.895 11.214 1.111 13.392 ;
     RECT  0.967 14.184 1.111 15.012 ;
     RECT  0.535 33.894 1.147 34.956 ;
     RECT  0.239 35.856 1.147 35.874 ;
     RECT  0.859 22.446 1.219 26.199 ;
     RECT  1.147 33.741 1.247 35.874 ;
     RECT  1.111 11.214 1.291 15.012 ;
     RECT  1.039 16.272 1.291 16.29 ;
     RECT  0.203 4.122 1.435 4.14 ;
     RECT  0.859 5.58 1.471 5.598 ;
     RECT  1.399 6.552 1.471 6.57 ;
     RECT  1.219 22.05 1.543 26.199 ;
     RECT  0.535 20.358 1.579 20.376 ;
     RECT  1.543 21.51 1.579 26.199 ;
     RECT  0.823 8.586 1.651 9.108 ;
     RECT  1.471 5.58 1.687 6.57 ;
     RECT  0.031 10.251 1.723 10.269 ;
     RECT  1.291 11.214 1.723 16.29 ;
     RECT  1.651 8.514 1.759 9.108 ;
     RECT  1.723 10.251 1.759 16.29 ;
     RECT  0.787 18.972 1.795 19.53 ;
     RECT  1.579 20.358 1.795 26.199 ;
     RECT  1.579 17.226 1.939 17.244 ;
     RECT  0.535 32.004 2.011 32.49 ;
     RECT  1.939 17.226 2.083 17.982 ;
     RECT  1.795 18.972 2.083 26.199 ;
     RECT  1.435 4.122 2.16 4.752 ;
     RECT  1.687 5.58 2.16 6.714 ;
     RECT  0.931 7.74 2.16 7.758 ;
     RECT  1.759 8.514 2.16 16.29 ;
     RECT  2.083 17.226 2.16 26.199 ;
     RECT  0.499 27.072 2.16 31.14 ;
     RECT  2.011 32.004 2.16 32.904 ;
     RECT  1.247 33.822 2.16 35.874 ;
     RECT  0.103 37.026 2.16 37.044 ;
     RECT  0.139 37.836 2.16 37.854 ;
     RECT  2.16 2.151 15.12 38.889 ;
     RECT  15.12 33.588 15.395 33.606 ;
     RECT  15.12 31.698 15.935 31.788 ;
     RECT  15.12 11.952 15.971 11.97 ;
     RECT  15.12 22.788 15.971 22.806 ;
     RECT  15.12 29.268 15.971 29.286 ;
     RECT  15.12 26.946 16.007 26.964 ;
     RECT  15.935 31.698 16.259 31.716 ;
     RECT  15.12 20.97 16.511 20.988 ;
     RECT  15.12 24.912 16.511 24.93 ;
     RECT  15.12 37.836 16.511 37.854 ;
    LAYER M3 ;
     RECT  0.108 2.059 0.126 2.237 ;
     RECT  3.384 2.059 3.402 2.299 ;
     RECT  2.415 2.143 2.505 2.395 ;
     RECT  2.304 2.395 2.505 2.413 ;
     RECT  3.384 2.299 3.546 2.413 ;
     RECT  5.115 2.143 5.205 2.413 ;
     RECT  7.815 2.143 7.905 2.413 ;
     RECT  10.515 2.143 10.605 2.413 ;
     RECT  13.215 2.143 13.305 2.413 ;
     RECT  7.815 2.413 8.097 2.491 ;
     RECT  2.304 2.413 3.546 2.587 ;
     RECT  7.092 2.491 8.097 2.725 ;
     RECT  6.696 2.725 8.097 2.765 ;
     RECT  5.115 2.413 5.397 2.827 ;
     RECT  6.84 2.765 8.097 2.861 ;
     RECT  7.092 2.861 8.097 3.181 ;
     RECT  8.928 0.091 8.946 3.181 ;
     RECT  2.304 2.587 4.014 3.271 ;
     RECT  2.304 3.271 4.122 3.307 ;
     RECT  5.115 2.827 5.742 3.307 ;
     RECT  2.304 3.307 5.742 3.643 ;
     RECT  7.092 3.181 8.946 3.643 ;
     RECT  0.144 3.211 0.162 3.691 ;
     RECT  0.144 3.691 0.198 3.739 ;
     RECT  0.108 3.739 0.198 4.117 ;
     RECT  0.108 4.117 0.27 4.301 ;
     RECT  0.144 4.301 0.27 4.363 ;
     RECT  2.304 3.643 8.946 4.495 ;
     RECT  1.98 4.495 8.946 4.729 ;
     RECT  0.144 4.363 0.342 5.117 ;
     RECT  0.252 5.117 0.342 5.575 ;
     RECT  1.44 4.729 8.946 5.575 ;
     RECT  0.252 5.575 8.946 5.851 ;
     RECT  0.18 5.851 8.946 5.899 ;
     RECT  0.108 5.899 8.946 6.461 ;
     RECT  0.252 6.461 8.946 7.483 ;
     RECT  0.144 7.483 8.946 7.661 ;
     RECT  17.172 7.531 17.19 7.661 ;
     RECT  0.216 7.661 8.946 7.757 ;
     RECT  0.108 8.581 0.126 8.923 ;
     RECT  0.864 7.757 8.946 8.923 ;
     RECT  0.108 8.923 8.946 9.485 ;
     RECT  0.18 9.485 8.946 9.533 ;
     RECT  12.168 7.627 12.186 9.787 ;
     RECT  17.172 9.691 17.19 9.821 ;
     RECT  0.036 10.246 0.054 10.555 ;
     RECT  0.828 9.533 8.946 10.555 ;
     RECT  15.948 11.851 15.966 11.975 ;
     RECT  12.168 9.787 12.366 12.091 ;
     RECT  13.215 2.413 13.497 12.091 ;
     RECT  0.036 10.555 8.946 13.199 ;
     RECT  0.072 13.199 8.946 16.231 ;
     RECT  14.472 14.011 14.49 17.083 ;
     RECT  0.036 16.231 8.946 17.177 ;
     RECT  14.472 17.083 14.778 17.491 ;
     RECT  14.472 17.491 14.922 17.549 ;
     RECT  14.472 17.549 14.49 18.331 ;
     RECT  0.072 17.177 8.946 18.841 ;
     RECT  0.072 18.841 8.982 19.039 ;
     RECT  0.072 19.039 9.558 20.011 ;
     RECT  10.515 2.413 10.797 20.011 ;
     RECT  12.168 12.091 13.497 20.461 ;
     RECT  16.236 16.171 16.254 20.491 ;
     RECT  12.168 20.461 13.554 20.551 ;
     RECT  0.072 20.011 10.797 20.615 ;
     RECT  11.736 20.551 13.554 20.885 ;
     RECT  16.236 20.491 16.506 20.993 ;
     RECT  0.072 20.615 9.558 21.541 ;
     RECT  10.515 20.615 10.797 21.541 ;
     RECT  11.736 20.885 12.438 21.811 ;
     RECT  0.072 21.541 10.797 22.513 ;
     RECT  0.072 22.513 10.854 22.613 ;
     RECT  11.664 21.811 12.438 22.621 ;
     RECT  13.215 20.885 13.554 22.621 ;
     RECT  16.236 20.993 16.254 22.651 ;
     RECT  0.072 22.613 10.797 22.711 ;
     RECT  15.948 22.651 16.254 22.811 ;
     RECT  0.036 22.711 10.797 23.665 ;
     RECT  11.664 22.621 13.554 23.665 ;
     RECT  14.472 18.331 15.102 24.701 ;
     RECT  16.236 22.811 16.254 24.811 ;
     RECT  16.236 24.811 16.506 24.935 ;
     RECT  14.472 24.701 14.814 25.043 ;
     RECT  0.036 23.665 13.554 25.861 ;
     RECT  0.036 25.861 13.662 26.023 ;
     RECT  14.472 25.043 14.49 26.023 ;
     RECT  0.036 26.023 14.49 26.249 ;
     RECT  16.236 24.935 16.254 26.941 ;
     RECT  15.984 26.941 16.254 27.005 ;
     RECT  0.036 26.249 13.734 27.985 ;
     RECT  14.472 26.249 14.49 27.985 ;
     RECT  0.036 27.985 14.598 28.481 ;
     RECT  0.072 28.481 14.598 29.029 ;
     RECT  16.236 27.005 16.254 29.131 ;
     RECT  15.948 29.131 16.254 29.291 ;
     RECT  0.072 29.029 14.922 29.875 ;
     RECT  0.072 29.875 14.994 30.029 ;
     RECT  0.072 30.029 14.922 30.847 ;
     RECT  16.236 29.291 16.254 31.291 ;
     RECT  0.036 30.847 14.922 31.483 ;
     RECT  15.912 31.291 16.254 31.721 ;
     RECT  15.912 31.721 15.93 31.793 ;
     RECT  0.036 31.483 14.994 31.919 ;
     RECT  0.036 31.919 14.886 32.881 ;
     RECT  0.036 32.881 15.03 33.583 ;
     RECT  0.036 33.583 15.39 35.384 ;
     RECT  0.072 35.384 15.39 35.429 ;
     RECT  0.108 35.429 15.39 35.645 ;
     RECT  0.108 35.645 15.03 36.029 ;
     RECT  0.108 36.029 1.242 36.269 ;
     RECT  0.108 36.269 0.162 36.461 ;
     RECT  1.98 36.029 15.03 36.779 ;
     RECT  1.98 36.779 14.994 37.355 ;
     RECT  0.108 36.461 0.126 37.387 ;
     RECT  0.9 36.269 1.242 37.387 ;
     RECT  0.108 37.387 1.242 37.517 ;
     RECT  0.9 37.517 1.242 37.805 ;
     RECT  16.488 37.771 16.506 37.859 ;
     RECT  1.98 37.355 14.922 37.997 ;
     RECT  1.152 37.805 1.242 38.141 ;
     RECT  1.224 38.141 1.242 38.203 ;
     RECT  1.224 38.203 1.35 38.237 ;
     RECT  1.332 38.237 1.35 38.333 ;
     RECT  2.268 37.997 14.922 38.435 ;
     RECT  2.304 38.435 14.922 38.479 ;
     RECT  0.108 37.517 0.162 38.525 ;
     RECT  0.144 38.525 0.162 38.621 ;
     RECT  2.304 38.479 14.994 38.669 ;
     RECT  2.304 38.669 14.958 38.741 ;
     RECT  2.304 38.741 14.31 38.861 ;
     RECT  2.34 38.861 14.31 39.341 ;
     RECT  12.312 39.341 14.31 39.437 ;
     RECT  8.496 39.341 11.178 39.869 ;
     RECT  12.312 39.437 13.014 39.869 ;
     RECT  2.772 39.341 2.898 39.917 ;
     RECT  4.896 39.341 6.102 39.917 ;
     RECT  7.056 39.341 7.074 39.917 ;
     RECT  8.496 39.869 10.998 39.917 ;
     RECT  12.312 39.869 12.798 39.917 ;
     RECT  14.076 39.437 14.31 39.917 ;
     RECT  2.88 39.917 2.898 40.445 ;
     RECT  8.496 39.917 9.018 40.493 ;
     RECT  14.292 39.917 14.31 40.493 ;
     RECT  5.652 39.917 5.67 40.925 ;
     RECT  8.496 40.493 8.514 40.925 ;
     RECT  10.044 39.917 10.062 40.925 ;
    LAYER M4 ;
     RECT  0.06 2.208 0.097 38.856 ;
     RECT  0.097 2.064 2.245 38.856 ;
     RECT  2.245 2.064 2.677 39.336 ;
     RECT  2.677 2.064 2.801 39.912 ;
     RECT  2.869 40.416 2.963 40.44 ;
     RECT  2.801 2.064 3.089 39.336 ;
     RECT  3.089 2.064 3.413 38.136 ;
     RECT  3.413 18.96 3.485 38.136 ;
     RECT  3.413 2.304 3.539 17.832 ;
     RECT  3.539 2.304 3.557 17.784 ;
     RECT  3.485 18.96 3.809 37.896 ;
     RECT  3.557 2.496 4.133 17.784 ;
     RECT  3.809 18.96 4.549 25.08 ;
     RECT  3.089 39.216 4.565 39.336 ;
     RECT  3.809 26.064 4.885 37.896 ;
     RECT  4.549 18.816 5.101 25.08 ;
     RECT  4.885 26.064 5.101 38.892 ;
     RECT  4.133 2.496 5.108 10.2 ;
     RECT  4.133 11.76 5.108 17.784 ;
     RECT  5.101 18.816 5.108 38.892 ;
     RECT  5.108 2.148 5.212 38.892 ;
     RECT  5.212 2.418 5.404 38.892 ;
     RECT  5.404 2.496 5.501 25.512 ;
     RECT  5.404 26.64 5.557 38.892 ;
     RECT  4.645 39.888 5.557 39.912 ;
     RECT  5.501 8.496 5.573 25.512 ;
     RECT  5.501 2.496 5.603 6.84 ;
     RECT  5.573 10.752 5.603 25.512 ;
     RECT  5.603 10.752 5.645 25.176 ;
     RECT  5.573 8.496 5.681 9.384 ;
     RECT  5.125 40.896 5.681 40.92 ;
     RECT  5.645 10.848 5.717 25.176 ;
     RECT  5.717 10.848 5.753 24.456 ;
     RECT  5.557 26.64 5.843 39.912 ;
     RECT  5.681 8.88 5.861 9.384 ;
     RECT  5.603 2.496 5.891 6.264 ;
     RECT  5.753 14.112 5.897 22.248 ;
     RECT  5.897 14.112 5.987 19.32 ;
     RECT  5.753 23.28 5.987 24.456 ;
     RECT  5.891 2.496 6.035 5.688 ;
     RECT  5.987 15.984 6.041 19.32 ;
     RECT  5.843 28.416 6.113 39.912 ;
     RECT  6.113 28.512 6.149 39.912 ;
     RECT  6.035 2.496 6.227 5.64 ;
     RECT  5.897 20.4 6.257 22.248 ;
     RECT  5.987 14.112 6.365 14.952 ;
     RECT  5.843 26.64 6.365 27.144 ;
     RECT  6.149 28.704 6.365 39.912 ;
     RECT  5.753 10.848 6.371 12.792 ;
     RECT  6.365 28.8 6.371 39.912 ;
     RECT  6.371 28.8 6.419 36.744 ;
     RECT  6.257 22.224 6.437 22.248 ;
     RECT  6.227 2.496 6.473 4.536 ;
     RECT  6.365 14.784 6.473 14.952 ;
     RECT  6.041 15.984 6.545 19.224 ;
     RECT  6.371 12.24 6.581 12.792 ;
     RECT  5.861 8.88 6.659 8.904 ;
     RECT  5.987 23.28 6.793 23.304 ;
     RECT  6.371 10.848 6.797 10.968 ;
     RECT  6.797 10.944 6.833 10.968 ;
     RECT  6.371 37.872 7.085 39.912 ;
     RECT  6.545 16.512 7.189 19.224 ;
     RECT  6.257 20.4 7.189 21.096 ;
     RECT  6.365 26.784 7.225 27.144 ;
     RECT  7.225 26.784 7.333 27.384 ;
     RECT  6.419 28.8 7.333 36.648 ;
     RECT  5.987 24.432 7.441 24.456 ;
     RECT  7.333 26.784 7.621 36.648 ;
     RECT  7.085 37.872 7.621 39.336 ;
     RECT  6.793 22.8 7.729 23.304 ;
     RECT  7.441 24.432 7.729 25.224 ;
     RECT  7.729 22.8 7.765 25.224 ;
     RECT  6.473 2.496 7.808 2.856 ;
     RECT  6.473 4.224 7.808 4.536 ;
     RECT  6.227 5.616 7.808 5.64 ;
     RECT  6.785 8.352 7.808 8.376 ;
     RECT  6.581 12.24 7.808 12.552 ;
     RECT  7.253 13.632 7.808 13.656 ;
     RECT  6.473 14.784 7.808 14.808 ;
     RECT  7.189 16.512 7.808 21.096 ;
     RECT  7.765 22.8 7.808 25.512 ;
     RECT  7.621 26.784 7.808 39.336 ;
     RECT  7.808 2.148 7.912 39.336 ;
     RECT  7.912 2.418 8.104 39.336 ;
     RECT  8.104 22.176 8.243 25.512 ;
     RECT  8.104 20.4 8.273 20.712 ;
     RECT  8.104 2.832 8.291 2.856 ;
     RECT  8.243 22.176 8.291 22.296 ;
     RECT  8.291 22.176 8.525 22.2 ;
     RECT  7.957 40.896 8.525 40.92 ;
     RECT  8.243 23.76 8.777 25.512 ;
     RECT  8.725 0.096 8.957 0.12 ;
     RECT  8.104 26.784 9.107 39.336 ;
     RECT  8.777 23.76 9.209 25.224 ;
     RECT  8.273 20.4 9.245 20.424 ;
     RECT  9.209 23.76 9.277 25.08 ;
     RECT  8.629 40.416 9.299 40.488 ;
     RECT  9.308 20.496 9.395 20.52 ;
     RECT  9.107 39.312 9.485 39.336 ;
     RECT  9.277 22.8 9.637 25.08 ;
     RECT  9.107 26.784 9.637 37.896 ;
     RECT  9.637 26.352 10.069 37.896 ;
     RECT  9.485 39.312 10.069 39.912 ;
     RECT  9.733 40.896 10.073 40.92 ;
     RECT  9.637 22.176 10.309 25.08 ;
     RECT  10.069 26.352 10.309 39.912 ;
     RECT  10.309 22.176 10.508 40.872 ;
     RECT  10.508 2.148 10.612 40.872 ;
     RECT  10.612 2.418 10.643 40.872 ;
     RECT  10.643 2.418 10.804 39.912 ;
     RECT  10.804 25.536 10.865 37.128 ;
     RECT  10.804 39.264 11.009 39.912 ;
     RECT  10.865 25.728 11.797 37.128 ;
     RECT  10.804 38.208 11.797 38.232 ;
     RECT  11.797 25.728 11.833 38.232 ;
     RECT  11.833 25.728 11.861 38.28 ;
     RECT  11.009 39.264 11.861 39.864 ;
     RECT  11.861 25.728 12.133 39.864 ;
     RECT  12.133 25.728 12.809 39.912 ;
     RECT  12.809 25.728 13.025 39.864 ;
     RECT  12.157 7.632 13.208 7.656 ;
     RECT  12.337 9.792 13.208 9.816 ;
     RECT  13.129 20.064 13.208 20.088 ;
     RECT  13.025 25.728 13.208 39.432 ;
     RECT  13.093 40.896 13.283 40.92 ;
     RECT  13.208 2.148 13.312 39.432 ;
     RECT  13.312 2.418 13.504 39.432 ;
     RECT  13.504 27.984 13.565 38.328 ;
     RECT  13.504 20.064 13.619 20.088 ;
     RECT  13.565 28.176 13.673 38.328 ;
     RECT  13.673 28.176 13.709 28.488 ;
     RECT  13.504 39.312 14.065 39.432 ;
     RECT  13.709 28.464 14.069 28.488 ;
     RECT  13.673 29.52 14.177 38.328 ;
     RECT  14.177 36 14.185 38.328 ;
     RECT  14.185 38.304 14.195 38.328 ;
     RECT  14.177 29.52 14.213 34.824 ;
     RECT  14.065 39.312 14.249 39.912 ;
     RECT  14.249 39.408 14.281 39.912 ;
     RECT  14.213 29.52 14.284 34.728 ;
     RECT  14.281 39.408 14.387 40.488 ;
     RECT  14.284 30.432 14.501 34.728 ;
     RECT  14.501 33.456 14.537 34.728 ;
     RECT  14.501 30.432 14.573 32.424 ;
     RECT  14.387 40.464 14.579 40.488 ;
     RECT  14.537 34.656 14.723 34.728 ;
     RECT  13.504 17.52 14.732 17.544 ;
     RECT  14.732 17.088 14.819 17.544 ;
     RECT  14.387 39.408 14.819 39.432 ;
     RECT  14.573 30.768 14.861 32.424 ;
     RECT  14.185 36 14.861 36.984 ;
     RECT  14.819 17.52 14.933 17.544 ;
     RECT  14.861 30.768 14.933 31.896 ;
     RECT  14.933 31.488 15.005 31.896 ;
     RECT  14.861 36.96 15.011 36.984 ;
     RECT  13.504 7.632 17.161 7.656 ;
     RECT  13.504 9.792 17.161 9.816 ;
    LAYER M5 ;
     RECT  8.64 0.016 8.76 0.131 ;
     RECT  8.64 0.131 8.664 2.137 ;
     RECT  2.4 2.137 2.52 2.151 ;
     RECT  5.1 2.137 5.22 2.151 ;
     RECT  10.5 2.137 10.62 2.151 ;
     RECT  13.2 2.137 13.32 2.151 ;
     RECT  7.8 2.137 8.664 4.453 ;
     RECT  6.864 4.453 8.664 4.501 ;
     RECT  0.144 4.309 0.168 5.027 ;
     RECT  5.1 2.151 5.412 5.029 ;
     RECT  6.48 4.501 8.664 5.029 ;
     RECT  13.2 2.151 13.512 5.365 ;
     RECT  5.1 5.029 8.664 5.605 ;
     RECT  2.4 2.151 2.712 6.133 ;
     RECT  2.4 6.133 3.48 6.229 ;
     RECT  4.56 5.605 8.664 6.229 ;
     RECT  2.4 6.229 8.664 7.381 ;
     RECT  0.144 8.773 0.168 9.059 ;
     RECT  2.208 7.381 8.664 14.149 ;
     RECT  1.968 14.149 8.664 15.973 ;
     RECT  1.056 15.973 8.664 16.213 ;
     RECT  0.192 16.213 8.664 16.403 ;
     RECT  1.056 16.403 8.664 17.123 ;
     RECT  14.784 3.205 14.808 17.123 ;
     RECT  13.2 5.365 13.608 17.509 ;
     RECT  1.968 17.123 8.664 17.603 ;
     RECT  2.208 17.603 8.664 20.485 ;
     RECT  0.144 21.925 0.168 22.067 ;
     RECT  2.208 20.485 9.384 22.165 ;
     RECT  10.5 2.151 10.812 22.165 ;
     RECT  0.144 23.365 0.168 23.651 ;
     RECT  2.208 22.165 10.812 26.099 ;
     RECT  2.256 26.099 10.812 26.149 ;
     RECT  2.256 26.149 11.016 26.197 ;
     RECT  2.256 26.197 11.736 26.677 ;
     RECT  2.256 26.677 11.784 27.301 ;
     RECT  13.2 17.509 14.184 27.301 ;
     RECT  2.256 27.301 14.184 29.509 ;
     RECT  2.256 29.509 14.232 30.371 ;
     RECT  0.24 30.325 0.264 30.467 ;
     RECT  2.4 30.371 14.232 30.757 ;
     RECT  2.4 30.757 14.808 31.381 ;
     RECT  2.304 31.381 14.808 31.955 ;
     RECT  2.304 31.955 14.328 32.003 ;
     RECT  0.144 32.773 0.168 34.405 ;
     RECT  2.4 32.003 14.328 34.405 ;
     RECT  2.4 34.405 14.52 34.645 ;
     RECT  0.144 34.405 0.216 34.837 ;
     RECT  2.4 34.645 14.712 35.075 ;
     RECT  4.512 35.075 14.712 35.363 ;
     RECT  2.4 35.075 3.432 35.699 ;
     RECT  4.512 35.363 8.568 35.987 ;
     RECT  4.848 35.987 8.568 36.371 ;
     RECT  4.848 36.371 6.408 36.755 ;
     RECT  7.68 36.371 8.568 36.901 ;
     RECT  9.552 35.363 14.712 36.901 ;
     RECT  7.68 36.901 14.712 36.949 ;
     RECT  2.4 35.699 3.336 36.997 ;
     RECT  4.848 36.755 6.36 36.997 ;
     RECT  7.68 36.949 15 37.043 ;
     RECT  9.552 37.043 15 37.139 ;
     RECT  2.4 36.997 6.36 37.331 ;
     RECT  7.68 37.043 8.568 37.379 ;
     RECT  0.144 34.837 0.264 37.619 ;
     RECT  7.8 37.379 8.568 37.667 ;
     RECT  9.552 37.139 10.812 37.667 ;
     RECT  0.24 37.619 0.264 37.715 ;
     RECT  9.744 37.667 10.812 37.907 ;
     RECT  11.808 37.139 15 37.907 ;
     RECT  11.856 37.907 15 38.291 ;
     RECT  11.904 38.291 15 38.339 ;
     RECT  2.4 37.331 5.412 38.773 ;
     RECT  7.8 37.667 8.112 38.773 ;
     RECT  10.224 37.907 10.812 39.205 ;
     RECT  2.4 38.773 6.024 39.253 ;
     RECT  7.8 38.773 9.096 39.253 ;
     RECT  10.176 39.205 10.812 39.253 ;
     RECT  11.904 38.339 13.512 39.253 ;
     RECT  2.4 39.253 9.096 39.301 ;
     RECT  10.176 39.253 13.512 39.301 ;
     RECT  2.256 39.301 13.944 39.349 ;
     RECT  14.976 38.339 15 39.349 ;
     RECT  2.256 39.349 15 40.976 ;
     RECT  13.512 3.205 14.725 3.288 ;
     RECT  13.512 3.288 14.784 5.328 ;
     RECT  5.412 4.453 6.864 4.501 ;
     RECT  5.412 4.501 6.48 5.029 ;
     RECT  13.608 5.448 14.784 13.968 ;
     RECT  3.48 6.133 4.56 6.229 ;
     RECT  13.608 14.088 14.784 17.123 ;
     RECT  13.608 17.123 14.184 17.509 ;
     RECT  9.384 20.485 10.5 22.165 ;
     RECT  0.144 22.067 0.168 23.365 ;
     RECT  11.736 26.197 13.2 26.677 ;
     RECT  11.784 26.677 13.2 27.301 ;
     RECT  2.304 30.371 2.4 31.381 ;
     RECT  3.432 35.075 4.512 35.699 ;
     RECT  8.568 35.363 9.552 36.901 ;
     RECT  3.336 35.699 4.512 35.987 ;
     RECT  3.336 35.987 4.848 36.997 ;
     RECT  6.408 36.371 7.68 36.755 ;
     RECT  6.36 36.755 7.68 37.331 ;
     RECT  8.568 37.043 9.552 37.667 ;
     RECT  10.812 37.139 11.808 37.907 ;
     RECT  5.412 37.331 6.024 38.773 ;
     RECT  8.112 37.667 9.744 37.907 ;
     RECT  8.112 37.907 10.224 38.773 ;
     RECT  10.812 37.907 11.856 38.291 ;
     RECT  10.812 38.291 11.904 39.253 ;
     RECT  13.512 38.339 14.976 39.301 ;
     RECT  9.096 38.773 10.224 39.205 ;
     RECT  9.096 39.205 10.176 39.301 ;
     RECT  13.944 39.301 14.976 39.349 ;
  END
END ot_s81_cfg7_seq
END LIBRARY
